VERSION 5.8 ;
BUSBITCHARS "[]" ;
DIVIDERCHAR "/" ;
UNITS
    DATABASE MICRONS 1000 ;
END UNITS

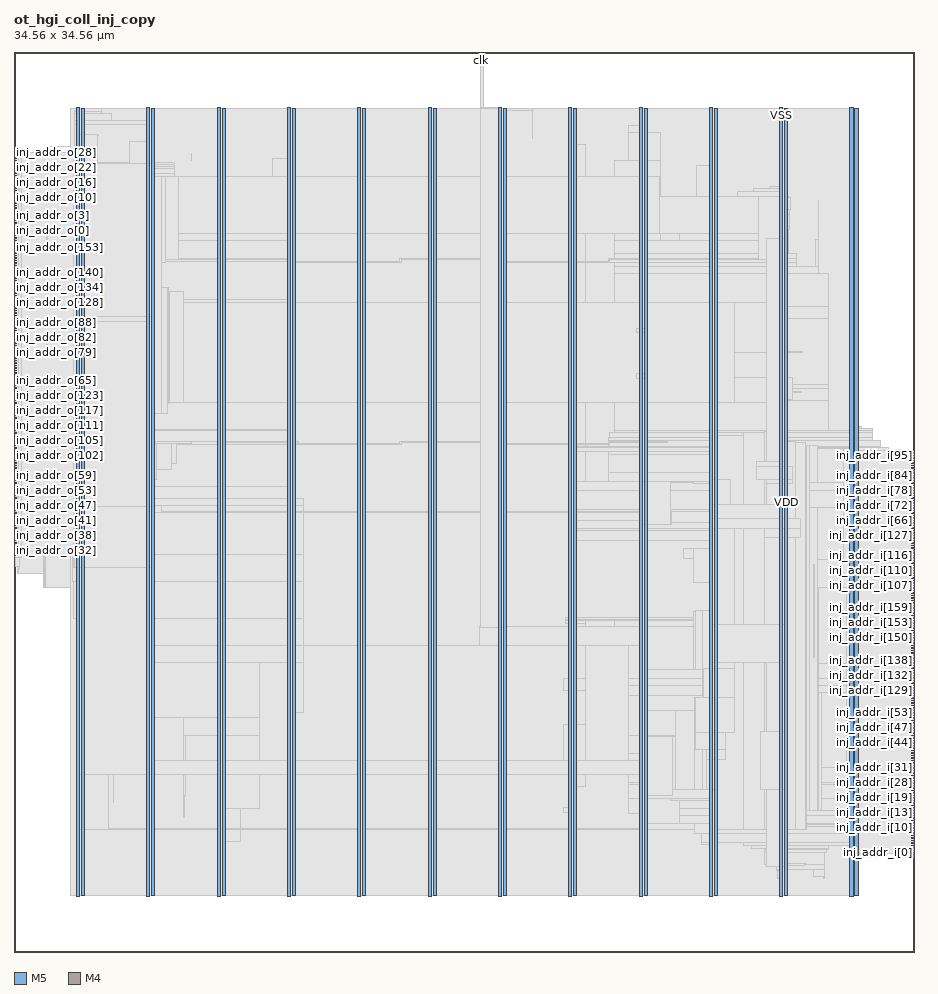
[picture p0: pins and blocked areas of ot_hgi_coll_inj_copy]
MACRO ot_hgi_coll_inj_copy
  FOREIGN ot_hgi_coll_inj_copy 0 0 ;
  CLASS BLOCK ;
  SIZE 34.56 BY 34.56 ;
  PIN clk
    DIRECTION INPUT ;
    USE SIGNAL ;
    PORT
      LAYER M5 ;
        RECT  17.904 34.476 17.928 34.56 ;
    END
  END clk
  PIN inj_addr_i[0]
    DIRECTION INPUT ;
    USE SIGNAL ;
    PORT
      LAYER M4 ;
        RECT  34.476 3.792 34.56 3.816 ;
    END
  END inj_addr_i[0]
  PIN inj_addr_i[100]
    DIRECTION INPUT ;
    USE SIGNAL ;
    PORT
      LAYER M4 ;
        RECT  34.476 13.392 34.56 13.416 ;
    END
  END inj_addr_i[100]
  PIN inj_addr_i[101]
    DIRECTION INPUT ;
    USE SIGNAL ;
    PORT
      LAYER M4 ;
        RECT  34.476 13.488 34.56 13.512 ;
    END
  END inj_addr_i[101]
  PIN inj_addr_i[102]
    DIRECTION INPUT ;
    USE SIGNAL ;
    PORT
      LAYER M4 ;
        RECT  34.476 13.584 34.56 13.608 ;
    END
  END inj_addr_i[102]
  PIN inj_addr_i[103]
    DIRECTION INPUT ;
    USE SIGNAL ;
    PORT
      LAYER M4 ;
        RECT  34.476 13.68 34.56 13.704 ;
    END
  END inj_addr_i[103]
  PIN inj_addr_i[104]
    DIRECTION INPUT ;
    USE SIGNAL ;
    PORT
      LAYER M4 ;
        RECT  34.476 13.776 34.56 13.8 ;
    END
  END inj_addr_i[104]
  PIN inj_addr_i[105]
    DIRECTION INPUT ;
    USE SIGNAL ;
    PORT
      LAYER M4 ;
        RECT  34.476 13.872 34.56 13.896 ;
    END
  END inj_addr_i[105]
  PIN inj_addr_i[106]
    DIRECTION INPUT ;
    USE SIGNAL ;
    PORT
      LAYER M4 ;
        RECT  34.476 13.968 34.56 13.992 ;
    END
  END inj_addr_i[106]
  PIN inj_addr_i[107]
    DIRECTION INPUT ;
    USE SIGNAL ;
    PORT
      LAYER M4 ;
        RECT  34.476 14.064 34.56 14.088 ;
    END
  END inj_addr_i[107]
  PIN inj_addr_i[108]
    DIRECTION INPUT ;
    USE SIGNAL ;
    PORT
      LAYER M4 ;
        RECT  34.476 14.16 34.56 14.184 ;
    END
  END inj_addr_i[108]
  PIN inj_addr_i[109]
    DIRECTION INPUT ;
    USE SIGNAL ;
    PORT
      LAYER M4 ;
        RECT  34.476 14.256 34.56 14.28 ;
    END
  END inj_addr_i[109]
  PIN inj_addr_i[10]
    DIRECTION INPUT ;
    USE SIGNAL ;
    PORT
      LAYER M4 ;
        RECT  34.476 4.752 34.56 4.776 ;
    END
  END inj_addr_i[10]
  PIN inj_addr_i[110]
    DIRECTION INPUT ;
    USE SIGNAL ;
    PORT
      LAYER M4 ;
        RECT  34.476 14.352 34.56 14.376 ;
    END
  END inj_addr_i[110]
  PIN inj_addr_i[111]
    DIRECTION INPUT ;
    USE SIGNAL ;
    PORT
      LAYER M4 ;
        RECT  34.476 14.448 34.56 14.472 ;
    END
  END inj_addr_i[111]
  PIN inj_addr_i[112]
    DIRECTION INPUT ;
    USE SIGNAL ;
    PORT
      LAYER M4 ;
        RECT  34.476 14.544 34.56 14.568 ;
    END
  END inj_addr_i[112]
  PIN inj_addr_i[113]
    DIRECTION INPUT ;
    USE SIGNAL ;
    PORT
      LAYER M4 ;
        RECT  34.476 14.64 34.56 14.664 ;
    END
  END inj_addr_i[113]
  PIN inj_addr_i[114]
    DIRECTION INPUT ;
    USE SIGNAL ;
    PORT
      LAYER M4 ;
        RECT  34.476 14.736 34.56 14.76 ;
    END
  END inj_addr_i[114]
  PIN inj_addr_i[115]
    DIRECTION INPUT ;
    USE SIGNAL ;
    PORT
      LAYER M4 ;
        RECT  34.476 14.832 34.56 14.856 ;
    END
  END inj_addr_i[115]
  PIN inj_addr_i[116]
    DIRECTION INPUT ;
    USE SIGNAL ;
    PORT
      LAYER M4 ;
        RECT  34.476 14.928 34.56 14.952 ;
    END
  END inj_addr_i[116]
  PIN inj_addr_i[117]
    DIRECTION INPUT ;
    USE SIGNAL ;
    PORT
      LAYER M4 ;
        RECT  34.476 15.024 34.56 15.048 ;
    END
  END inj_addr_i[117]
  PIN inj_addr_i[118]
    DIRECTION INPUT ;
    USE SIGNAL ;
    PORT
      LAYER M4 ;
        RECT  34.476 15.12 34.56 15.144 ;
    END
  END inj_addr_i[118]
  PIN inj_addr_i[119]
    DIRECTION INPUT ;
    USE SIGNAL ;
    PORT
      LAYER M4 ;
        RECT  34.476 15.216 34.56 15.24 ;
    END
  END inj_addr_i[119]
  PIN inj_addr_i[11]
    DIRECTION INPUT ;
    USE SIGNAL ;
    PORT
      LAYER M4 ;
        RECT  34.476 4.848 34.56 4.872 ;
    END
  END inj_addr_i[11]
  PIN inj_addr_i[120]
    DIRECTION INPUT ;
    USE SIGNAL ;
    PORT
      LAYER M4 ;
        RECT  34.476 15.312 34.56 15.336 ;
    END
  END inj_addr_i[120]
  PIN inj_addr_i[121]
    DIRECTION INPUT ;
    USE SIGNAL ;
    PORT
      LAYER M4 ;
        RECT  34.476 15.408 34.56 15.432 ;
    END
  END inj_addr_i[121]
  PIN inj_addr_i[122]
    DIRECTION INPUT ;
    USE SIGNAL ;
    PORT
      LAYER M4 ;
        RECT  34.476 15.504 34.56 15.528 ;
    END
  END inj_addr_i[122]
  PIN inj_addr_i[123]
    DIRECTION INPUT ;
    USE SIGNAL ;
    PORT
      LAYER M4 ;
        RECT  34.476 15.6 34.56 15.624 ;
    END
  END inj_addr_i[123]
  PIN inj_addr_i[124]
    DIRECTION INPUT ;
    USE SIGNAL ;
    PORT
      LAYER M4 ;
        RECT  34.476 15.696 34.56 15.72 ;
    END
  END inj_addr_i[124]
  PIN inj_addr_i[125]
    DIRECTION INPUT ;
    USE SIGNAL ;
    PORT
      LAYER M4 ;
        RECT  34.476 15.792 34.56 15.816 ;
    END
  END inj_addr_i[125]
  PIN inj_addr_i[126]
    DIRECTION INPUT ;
    USE SIGNAL ;
    PORT
      LAYER M4 ;
        RECT  34.476 15.888 34.56 15.912 ;
    END
  END inj_addr_i[126]
  PIN inj_addr_i[127]
    DIRECTION INPUT ;
    USE SIGNAL ;
    PORT
      LAYER M4 ;
        RECT  34.476 15.984 34.56 16.008 ;
    END
  END inj_addr_i[127]
  PIN inj_addr_i[128]
    DIRECTION INPUT ;
    USE SIGNAL ;
    PORT
      LAYER M4 ;
        RECT  34.476 9.936 34.56 9.96 ;
    END
  END inj_addr_i[128]
  PIN inj_addr_i[129]
    DIRECTION INPUT ;
    USE SIGNAL ;
    PORT
      LAYER M4 ;
        RECT  34.476 10.032 34.56 10.056 ;
    END
  END inj_addr_i[129]
  PIN inj_addr_i[12]
    DIRECTION INPUT ;
    USE SIGNAL ;
    PORT
      LAYER M4 ;
        RECT  34.476 4.944 34.56 4.968 ;
    END
  END inj_addr_i[12]
  PIN inj_addr_i[130]
    DIRECTION INPUT ;
    USE SIGNAL ;
    PORT
      LAYER M4 ;
        RECT  34.476 10.128 34.56 10.152 ;
    END
  END inj_addr_i[130]
  PIN inj_addr_i[131]
    DIRECTION INPUT ;
    USE SIGNAL ;
    PORT
      LAYER M4 ;
        RECT  34.476 10.224 34.56 10.248 ;
    END
  END inj_addr_i[131]
  PIN inj_addr_i[132]
    DIRECTION INPUT ;
    USE SIGNAL ;
    PORT
      LAYER M4 ;
        RECT  34.476 10.32 34.56 10.344 ;
    END
  END inj_addr_i[132]
  PIN inj_addr_i[133]
    DIRECTION INPUT ;
    USE SIGNAL ;
    PORT
      LAYER M4 ;
        RECT  34.476 10.416 34.56 10.44 ;
    END
  END inj_addr_i[133]
  PIN inj_addr_i[134]
    DIRECTION INPUT ;
    USE SIGNAL ;
    PORT
      LAYER M4 ;
        RECT  34.476 10.512 34.56 10.536 ;
    END
  END inj_addr_i[134]
  PIN inj_addr_i[135]
    DIRECTION INPUT ;
    USE SIGNAL ;
    PORT
      LAYER M4 ;
        RECT  34.476 10.608 34.56 10.632 ;
    END
  END inj_addr_i[135]
  PIN inj_addr_i[136]
    DIRECTION INPUT ;
    USE SIGNAL ;
    PORT
      LAYER M4 ;
        RECT  34.476 10.704 34.56 10.728 ;
    END
  END inj_addr_i[136]
  PIN inj_addr_i[137]
    DIRECTION INPUT ;
    USE SIGNAL ;
    PORT
      LAYER M4 ;
        RECT  34.476 10.8 34.56 10.824 ;
    END
  END inj_addr_i[137]
  PIN inj_addr_i[138]
    DIRECTION INPUT ;
    USE SIGNAL ;
    PORT
      LAYER M4 ;
        RECT  34.476 10.896 34.56 10.92 ;
    END
  END inj_addr_i[138]
  PIN inj_addr_i[139]
    DIRECTION INPUT ;
    USE SIGNAL ;
    PORT
      LAYER M4 ;
        RECT  34.476 10.992 34.56 11.016 ;
    END
  END inj_addr_i[139]
  PIN inj_addr_i[13]
    DIRECTION INPUT ;
    USE SIGNAL ;
    PORT
      LAYER M4 ;
        RECT  34.476 5.04 34.56 5.064 ;
    END
  END inj_addr_i[13]
  PIN inj_addr_i[140]
    DIRECTION INPUT ;
    USE SIGNAL ;
    PORT
      LAYER M4 ;
        RECT  34.476 11.088 34.56 11.112 ;
    END
  END inj_addr_i[140]
  PIN inj_addr_i[141]
    DIRECTION INPUT ;
    USE SIGNAL ;
    PORT
      LAYER M4 ;
        RECT  34.476 11.184 34.56 11.208 ;
    END
  END inj_addr_i[141]
  PIN inj_addr_i[142]
    DIRECTION INPUT ;
    USE SIGNAL ;
    PORT
      LAYER M4 ;
        RECT  34.476 11.28 34.56 11.304 ;
    END
  END inj_addr_i[142]
  PIN inj_addr_i[143]
    DIRECTION INPUT ;
    USE SIGNAL ;
    PORT
      LAYER M4 ;
        RECT  34.476 11.376 34.56 11.4 ;
    END
  END inj_addr_i[143]
  PIN inj_addr_i[144]
    DIRECTION INPUT ;
    USE SIGNAL ;
    PORT
      LAYER M4 ;
        RECT  34.476 11.472 34.56 11.496 ;
    END
  END inj_addr_i[144]
  PIN inj_addr_i[145]
    DIRECTION INPUT ;
    USE SIGNAL ;
    PORT
      LAYER M4 ;
        RECT  34.476 11.568 34.56 11.592 ;
    END
  END inj_addr_i[145]
  PIN inj_addr_i[146]
    DIRECTION INPUT ;
    USE SIGNAL ;
    PORT
      LAYER M4 ;
        RECT  34.476 11.664 34.56 11.688 ;
    END
  END inj_addr_i[146]
  PIN inj_addr_i[147]
    DIRECTION INPUT ;
    USE SIGNAL ;
    PORT
      LAYER M4 ;
        RECT  34.476 11.76 34.56 11.784 ;
    END
  END inj_addr_i[147]
  PIN inj_addr_i[148]
    DIRECTION INPUT ;
    USE SIGNAL ;
    PORT
      LAYER M4 ;
        RECT  34.476 11.856 34.56 11.88 ;
    END
  END inj_addr_i[148]
  PIN inj_addr_i[149]
    DIRECTION INPUT ;
    USE SIGNAL ;
    PORT
      LAYER M4 ;
        RECT  34.476 11.952 34.56 11.976 ;
    END
  END inj_addr_i[149]
  PIN inj_addr_i[14]
    DIRECTION INPUT ;
    USE SIGNAL ;
    PORT
      LAYER M4 ;
        RECT  34.476 5.136 34.56 5.16 ;
    END
  END inj_addr_i[14]
  PIN inj_addr_i[150]
    DIRECTION INPUT ;
    USE SIGNAL ;
    PORT
      LAYER M4 ;
        RECT  34.476 12.048 34.56 12.072 ;
    END
  END inj_addr_i[150]
  PIN inj_addr_i[151]
    DIRECTION INPUT ;
    USE SIGNAL ;
    PORT
      LAYER M4 ;
        RECT  34.476 12.144 34.56 12.168 ;
    END
  END inj_addr_i[151]
  PIN inj_addr_i[152]
    DIRECTION INPUT ;
    USE SIGNAL ;
    PORT
      LAYER M4 ;
        RECT  34.476 12.24 34.56 12.264 ;
    END
  END inj_addr_i[152]
  PIN inj_addr_i[153]
    DIRECTION INPUT ;
    USE SIGNAL ;
    PORT
      LAYER M4 ;
        RECT  34.476 12.336 34.56 12.36 ;
    END
  END inj_addr_i[153]
  PIN inj_addr_i[154]
    DIRECTION INPUT ;
    USE SIGNAL ;
    PORT
      LAYER M4 ;
        RECT  34.476 12.432 34.56 12.456 ;
    END
  END inj_addr_i[154]
  PIN inj_addr_i[155]
    DIRECTION INPUT ;
    USE SIGNAL ;
    PORT
      LAYER M4 ;
        RECT  34.476 12.528 34.56 12.552 ;
    END
  END inj_addr_i[155]
  PIN inj_addr_i[156]
    DIRECTION INPUT ;
    USE SIGNAL ;
    PORT
      LAYER M4 ;
        RECT  34.476 12.624 34.56 12.648 ;
    END
  END inj_addr_i[156]
  PIN inj_addr_i[157]
    DIRECTION INPUT ;
    USE SIGNAL ;
    PORT
      LAYER M4 ;
        RECT  34.476 12.72 34.56 12.744 ;
    END
  END inj_addr_i[157]
  PIN inj_addr_i[158]
    DIRECTION INPUT ;
    USE SIGNAL ;
    PORT
      LAYER M4 ;
        RECT  34.476 12.816 34.56 12.84 ;
    END
  END inj_addr_i[158]
  PIN inj_addr_i[159]
    DIRECTION INPUT ;
    USE SIGNAL ;
    PORT
      LAYER M4 ;
        RECT  34.476 12.912 34.56 12.936 ;
    END
  END inj_addr_i[159]
  PIN inj_addr_i[15]
    DIRECTION INPUT ;
    USE SIGNAL ;
    PORT
      LAYER M4 ;
        RECT  34.476 5.232 34.56 5.256 ;
    END
  END inj_addr_i[15]
  PIN inj_addr_i[16]
    DIRECTION INPUT ;
    USE SIGNAL ;
    PORT
      LAYER M4 ;
        RECT  34.476 5.328 34.56 5.352 ;
    END
  END inj_addr_i[16]
  PIN inj_addr_i[17]
    DIRECTION INPUT ;
    USE SIGNAL ;
    PORT
      LAYER M4 ;
        RECT  34.476 5.424 34.56 5.448 ;
    END
  END inj_addr_i[17]
  PIN inj_addr_i[18]
    DIRECTION INPUT ;
    USE SIGNAL ;
    PORT
      LAYER M4 ;
        RECT  34.476 5.52 34.56 5.544 ;
    END
  END inj_addr_i[18]
  PIN inj_addr_i[19]
    DIRECTION INPUT ;
    USE SIGNAL ;
    PORT
      LAYER M4 ;
        RECT  34.476 5.616 34.56 5.64 ;
    END
  END inj_addr_i[19]
  PIN inj_addr_i[1]
    DIRECTION INPUT ;
    USE SIGNAL ;
    PORT
      LAYER M4 ;
        RECT  34.476 3.888 34.56 3.912 ;
    END
  END inj_addr_i[1]
  PIN inj_addr_i[20]
    DIRECTION INPUT ;
    USE SIGNAL ;
    PORT
      LAYER M4 ;
        RECT  34.476 5.712 34.56 5.736 ;
    END
  END inj_addr_i[20]
  PIN inj_addr_i[21]
    DIRECTION INPUT ;
    USE SIGNAL ;
    PORT
      LAYER M4 ;
        RECT  34.476 5.808 34.56 5.832 ;
    END
  END inj_addr_i[21]
  PIN inj_addr_i[22]
    DIRECTION INPUT ;
    USE SIGNAL ;
    PORT
      LAYER M4 ;
        RECT  34.476 5.904 34.56 5.928 ;
    END
  END inj_addr_i[22]
  PIN inj_addr_i[23]
    DIRECTION INPUT ;
    USE SIGNAL ;
    PORT
      LAYER M4 ;
        RECT  34.476 6 34.56 6.024 ;
    END
  END inj_addr_i[23]
  PIN inj_addr_i[24]
    DIRECTION INPUT ;
    USE SIGNAL ;
    PORT
      LAYER M4 ;
        RECT  34.476 6.096 34.56 6.12 ;
    END
  END inj_addr_i[24]
  PIN inj_addr_i[25]
    DIRECTION INPUT ;
    USE SIGNAL ;
    PORT
      LAYER M4 ;
        RECT  34.476 6.192 34.56 6.216 ;
    END
  END inj_addr_i[25]
  PIN inj_addr_i[26]
    DIRECTION INPUT ;
    USE SIGNAL ;
    PORT
      LAYER M4 ;
        RECT  34.476 6.288 34.56 6.312 ;
    END
  END inj_addr_i[26]
  PIN inj_addr_i[27]
    DIRECTION INPUT ;
    USE SIGNAL ;
    PORT
      LAYER M4 ;
        RECT  34.476 6.384 34.56 6.408 ;
    END
  END inj_addr_i[27]
  PIN inj_addr_i[28]
    DIRECTION INPUT ;
    USE SIGNAL ;
    PORT
      LAYER M4 ;
        RECT  34.476 6.48 34.56 6.504 ;
    END
  END inj_addr_i[28]
  PIN inj_addr_i[29]
    DIRECTION INPUT ;
    USE SIGNAL ;
    PORT
      LAYER M4 ;
        RECT  34.476 6.576 34.56 6.6 ;
    END
  END inj_addr_i[29]
  PIN inj_addr_i[2]
    DIRECTION INPUT ;
    USE SIGNAL ;
    PORT
      LAYER M4 ;
        RECT  34.476 3.984 34.56 4.008 ;
    END
  END inj_addr_i[2]
  PIN inj_addr_i[30]
    DIRECTION INPUT ;
    USE SIGNAL ;
    PORT
      LAYER M4 ;
        RECT  34.476 6.672 34.56 6.696 ;
    END
  END inj_addr_i[30]
  PIN inj_addr_i[31]
    DIRECTION INPUT ;
    USE SIGNAL ;
    PORT
      LAYER M4 ;
        RECT  34.476 6.768 34.56 6.792 ;
    END
  END inj_addr_i[31]
  PIN inj_addr_i[32]
    DIRECTION INPUT ;
    USE SIGNAL ;
    PORT
      LAYER M4 ;
        RECT  34.476 6.864 34.56 6.888 ;
    END
  END inj_addr_i[32]
  PIN inj_addr_i[33]
    DIRECTION INPUT ;
    USE SIGNAL ;
    PORT
      LAYER M4 ;
        RECT  34.476 6.96 34.56 6.984 ;
    END
  END inj_addr_i[33]
  PIN inj_addr_i[34]
    DIRECTION INPUT ;
    USE SIGNAL ;
    PORT
      LAYER M4 ;
        RECT  34.476 7.056 34.56 7.08 ;
    END
  END inj_addr_i[34]
  PIN inj_addr_i[35]
    DIRECTION INPUT ;
    USE SIGNAL ;
    PORT
      LAYER M4 ;
        RECT  34.476 7.152 34.56 7.176 ;
    END
  END inj_addr_i[35]
  PIN inj_addr_i[36]
    DIRECTION INPUT ;
    USE SIGNAL ;
    PORT
      LAYER M4 ;
        RECT  34.476 7.248 34.56 7.272 ;
    END
  END inj_addr_i[36]
  PIN inj_addr_i[37]
    DIRECTION INPUT ;
    USE SIGNAL ;
    PORT
      LAYER M4 ;
        RECT  34.476 7.344 34.56 7.368 ;
    END
  END inj_addr_i[37]
  PIN inj_addr_i[38]
    DIRECTION INPUT ;
    USE SIGNAL ;
    PORT
      LAYER M4 ;
        RECT  34.476 7.44 34.56 7.464 ;
    END
  END inj_addr_i[38]
  PIN inj_addr_i[39]
    DIRECTION INPUT ;
    USE SIGNAL ;
    PORT
      LAYER M4 ;
        RECT  34.476 7.536 34.56 7.56 ;
    END
  END inj_addr_i[39]
  PIN inj_addr_i[3]
    DIRECTION INPUT ;
    USE SIGNAL ;
    PORT
      LAYER M4 ;
        RECT  34.476 4.08 34.56 4.104 ;
    END
  END inj_addr_i[3]
  PIN inj_addr_i[40]
    DIRECTION INPUT ;
    USE SIGNAL ;
    PORT
      LAYER M4 ;
        RECT  34.476 7.632 34.56 7.656 ;
    END
  END inj_addr_i[40]
  PIN inj_addr_i[41]
    DIRECTION INPUT ;
    USE SIGNAL ;
    PORT
      LAYER M4 ;
        RECT  34.476 7.728 34.56 7.752 ;
    END
  END inj_addr_i[41]
  PIN inj_addr_i[42]
    DIRECTION INPUT ;
    USE SIGNAL ;
    PORT
      LAYER M4 ;
        RECT  34.476 7.824 34.56 7.848 ;
    END
  END inj_addr_i[42]
  PIN inj_addr_i[43]
    DIRECTION INPUT ;
    USE SIGNAL ;
    PORT
      LAYER M4 ;
        RECT  34.476 7.92 34.56 7.944 ;
    END
  END inj_addr_i[43]
  PIN inj_addr_i[44]
    DIRECTION INPUT ;
    USE SIGNAL ;
    PORT
      LAYER M4 ;
        RECT  34.476 8.016 34.56 8.04 ;
    END
  END inj_addr_i[44]
  PIN inj_addr_i[45]
    DIRECTION INPUT ;
    USE SIGNAL ;
    PORT
      LAYER M4 ;
        RECT  34.476 8.112 34.56 8.136 ;
    END
  END inj_addr_i[45]
  PIN inj_addr_i[46]
    DIRECTION INPUT ;
    USE SIGNAL ;
    PORT
      LAYER M4 ;
        RECT  34.476 8.208 34.56 8.232 ;
    END
  END inj_addr_i[46]
  PIN inj_addr_i[47]
    DIRECTION INPUT ;
    USE SIGNAL ;
    PORT
      LAYER M4 ;
        RECT  34.476 8.304 34.56 8.328 ;
    END
  END inj_addr_i[47]
  PIN inj_addr_i[48]
    DIRECTION INPUT ;
    USE SIGNAL ;
    PORT
      LAYER M4 ;
        RECT  34.476 8.4 34.56 8.424 ;
    END
  END inj_addr_i[48]
  PIN inj_addr_i[49]
    DIRECTION INPUT ;
    USE SIGNAL ;
    PORT
      LAYER M4 ;
        RECT  34.476 8.496 34.56 8.52 ;
    END
  END inj_addr_i[49]
  PIN inj_addr_i[4]
    DIRECTION INPUT ;
    USE SIGNAL ;
    PORT
      LAYER M4 ;
        RECT  34.476 4.176 34.56 4.2 ;
    END
  END inj_addr_i[4]
  PIN inj_addr_i[50]
    DIRECTION INPUT ;
    USE SIGNAL ;
    PORT
      LAYER M4 ;
        RECT  34.476 8.592 34.56 8.616 ;
    END
  END inj_addr_i[50]
  PIN inj_addr_i[51]
    DIRECTION INPUT ;
    USE SIGNAL ;
    PORT
      LAYER M4 ;
        RECT  34.476 8.688 34.56 8.712 ;
    END
  END inj_addr_i[51]
  PIN inj_addr_i[52]
    DIRECTION INPUT ;
    USE SIGNAL ;
    PORT
      LAYER M4 ;
        RECT  34.476 8.784 34.56 8.808 ;
    END
  END inj_addr_i[52]
  PIN inj_addr_i[53]
    DIRECTION INPUT ;
    USE SIGNAL ;
    PORT
      LAYER M4 ;
        RECT  34.476 8.88 34.56 8.904 ;
    END
  END inj_addr_i[53]
  PIN inj_addr_i[54]
    DIRECTION INPUT ;
    USE SIGNAL ;
    PORT
      LAYER M4 ;
        RECT  34.476 8.976 34.56 9 ;
    END
  END inj_addr_i[54]
  PIN inj_addr_i[55]
    DIRECTION INPUT ;
    USE SIGNAL ;
    PORT
      LAYER M4 ;
        RECT  34.476 9.072 34.56 9.096 ;
    END
  END inj_addr_i[55]
  PIN inj_addr_i[56]
    DIRECTION INPUT ;
    USE SIGNAL ;
    PORT
      LAYER M4 ;
        RECT  34.476 9.168 34.56 9.192 ;
    END
  END inj_addr_i[56]
  PIN inj_addr_i[57]
    DIRECTION INPUT ;
    USE SIGNAL ;
    PORT
      LAYER M4 ;
        RECT  34.476 9.264 34.56 9.288 ;
    END
  END inj_addr_i[57]
  PIN inj_addr_i[58]
    DIRECTION INPUT ;
    USE SIGNAL ;
    PORT
      LAYER M4 ;
        RECT  34.476 9.36 34.56 9.384 ;
    END
  END inj_addr_i[58]
  PIN inj_addr_i[59]
    DIRECTION INPUT ;
    USE SIGNAL ;
    PORT
      LAYER M4 ;
        RECT  34.476 9.456 34.56 9.48 ;
    END
  END inj_addr_i[59]
  PIN inj_addr_i[5]
    DIRECTION INPUT ;
    USE SIGNAL ;
    PORT
      LAYER M4 ;
        RECT  34.476 4.272 34.56 4.296 ;
    END
  END inj_addr_i[5]
  PIN inj_addr_i[60]
    DIRECTION INPUT ;
    USE SIGNAL ;
    PORT
      LAYER M4 ;
        RECT  34.476 9.552 34.56 9.576 ;
    END
  END inj_addr_i[60]
  PIN inj_addr_i[61]
    DIRECTION INPUT ;
    USE SIGNAL ;
    PORT
      LAYER M4 ;
        RECT  34.476 9.648 34.56 9.672 ;
    END
  END inj_addr_i[61]
  PIN inj_addr_i[62]
    DIRECTION INPUT ;
    USE SIGNAL ;
    PORT
      LAYER M4 ;
        RECT  34.476 9.744 34.56 9.768 ;
    END
  END inj_addr_i[62]
  PIN inj_addr_i[63]
    DIRECTION INPUT ;
    USE SIGNAL ;
    PORT
      LAYER M4 ;
        RECT  34.476 9.84 34.56 9.864 ;
    END
  END inj_addr_i[63]
  PIN inj_addr_i[64]
    DIRECTION INPUT ;
    USE SIGNAL ;
    PORT
      LAYER M4 ;
        RECT  34.476 16.08 34.56 16.104 ;
    END
  END inj_addr_i[64]
  PIN inj_addr_i[65]
    DIRECTION INPUT ;
    USE SIGNAL ;
    PORT
      LAYER M4 ;
        RECT  34.476 16.176 34.56 16.2 ;
    END
  END inj_addr_i[65]
  PIN inj_addr_i[66]
    DIRECTION INPUT ;
    USE SIGNAL ;
    PORT
      LAYER M4 ;
        RECT  34.476 16.272 34.56 16.296 ;
    END
  END inj_addr_i[66]
  PIN inj_addr_i[67]
    DIRECTION INPUT ;
    USE SIGNAL ;
    PORT
      LAYER M4 ;
        RECT  34.476 16.368 34.56 16.392 ;
    END
  END inj_addr_i[67]
  PIN inj_addr_i[68]
    DIRECTION INPUT ;
    USE SIGNAL ;
    PORT
      LAYER M4 ;
        RECT  34.476 16.464 34.56 16.488 ;
    END
  END inj_addr_i[68]
  PIN inj_addr_i[69]
    DIRECTION INPUT ;
    USE SIGNAL ;
    PORT
      LAYER M4 ;
        RECT  34.476 16.56 34.56 16.584 ;
    END
  END inj_addr_i[69]
  PIN inj_addr_i[6]
    DIRECTION INPUT ;
    USE SIGNAL ;
    PORT
      LAYER M4 ;
        RECT  34.476 4.368 34.56 4.392 ;
    END
  END inj_addr_i[6]
  PIN inj_addr_i[70]
    DIRECTION INPUT ;
    USE SIGNAL ;
    PORT
      LAYER M4 ;
        RECT  34.476 16.656 34.56 16.68 ;
    END
  END inj_addr_i[70]
  PIN inj_addr_i[71]
    DIRECTION INPUT ;
    USE SIGNAL ;
    PORT
      LAYER M4 ;
        RECT  34.476 16.752 34.56 16.776 ;
    END
  END inj_addr_i[71]
  PIN inj_addr_i[72]
    DIRECTION INPUT ;
    USE SIGNAL ;
    PORT
      LAYER M4 ;
        RECT  34.476 16.848 34.56 16.872 ;
    END
  END inj_addr_i[72]
  PIN inj_addr_i[73]
    DIRECTION INPUT ;
    USE SIGNAL ;
    PORT
      LAYER M4 ;
        RECT  34.476 16.944 34.56 16.968 ;
    END
  END inj_addr_i[73]
  PIN inj_addr_i[74]
    DIRECTION INPUT ;
    USE SIGNAL ;
    PORT
      LAYER M4 ;
        RECT  34.476 17.04 34.56 17.064 ;
    END
  END inj_addr_i[74]
  PIN inj_addr_i[75]
    DIRECTION INPUT ;
    USE SIGNAL ;
    PORT
      LAYER M4 ;
        RECT  34.476 17.136 34.56 17.16 ;
    END
  END inj_addr_i[75]
  PIN inj_addr_i[76]
    DIRECTION INPUT ;
    USE SIGNAL ;
    PORT
      LAYER M4 ;
        RECT  34.476 17.232 34.56 17.256 ;
    END
  END inj_addr_i[76]
  PIN inj_addr_i[77]
    DIRECTION INPUT ;
    USE SIGNAL ;
    PORT
      LAYER M4 ;
        RECT  34.476 17.328 34.56 17.352 ;
    END
  END inj_addr_i[77]
  PIN inj_addr_i[78]
    DIRECTION INPUT ;
    USE SIGNAL ;
    PORT
      LAYER M4 ;
        RECT  34.476 17.424 34.56 17.448 ;
    END
  END inj_addr_i[78]
  PIN inj_addr_i[79]
    DIRECTION INPUT ;
    USE SIGNAL ;
    PORT
      LAYER M4 ;
        RECT  34.476 17.52 34.56 17.544 ;
    END
  END inj_addr_i[79]
  PIN inj_addr_i[7]
    DIRECTION INPUT ;
    USE SIGNAL ;
    PORT
      LAYER M4 ;
        RECT  34.476 4.464 34.56 4.488 ;
    END
  END inj_addr_i[7]
  PIN inj_addr_i[80]
    DIRECTION INPUT ;
    USE SIGNAL ;
    PORT
      LAYER M4 ;
        RECT  34.476 17.616 34.56 17.64 ;
    END
  END inj_addr_i[80]
  PIN inj_addr_i[81]
    DIRECTION INPUT ;
    USE SIGNAL ;
    PORT
      LAYER M4 ;
        RECT  34.476 17.712 34.56 17.736 ;
    END
  END inj_addr_i[81]
  PIN inj_addr_i[82]
    DIRECTION INPUT ;
    USE SIGNAL ;
    PORT
      LAYER M4 ;
        RECT  34.476 17.808 34.56 17.832 ;
    END
  END inj_addr_i[82]
  PIN inj_addr_i[83]
    DIRECTION INPUT ;
    USE SIGNAL ;
    PORT
      LAYER M4 ;
        RECT  34.476 17.904 34.56 17.928 ;
    END
  END inj_addr_i[83]
  PIN inj_addr_i[84]
    DIRECTION INPUT ;
    USE SIGNAL ;
    PORT
      LAYER M4 ;
        RECT  34.476 18 34.56 18.024 ;
    END
  END inj_addr_i[84]
  PIN inj_addr_i[85]
    DIRECTION INPUT ;
    USE SIGNAL ;
    PORT
      LAYER M4 ;
        RECT  34.476 18.096 34.56 18.12 ;
    END
  END inj_addr_i[85]
  PIN inj_addr_i[86]
    DIRECTION INPUT ;
    USE SIGNAL ;
    PORT
      LAYER M4 ;
        RECT  34.476 18.192 34.56 18.216 ;
    END
  END inj_addr_i[86]
  PIN inj_addr_i[87]
    DIRECTION INPUT ;
    USE SIGNAL ;
    PORT
      LAYER M4 ;
        RECT  34.476 18.288 34.56 18.312 ;
    END
  END inj_addr_i[87]
  PIN inj_addr_i[88]
    DIRECTION INPUT ;
    USE SIGNAL ;
    PORT
      LAYER M4 ;
        RECT  34.476 18.384 34.56 18.408 ;
    END
  END inj_addr_i[88]
  PIN inj_addr_i[89]
    DIRECTION INPUT ;
    USE SIGNAL ;
    PORT
      LAYER M4 ;
        RECT  34.476 18.48 34.56 18.504 ;
    END
  END inj_addr_i[89]
  PIN inj_addr_i[8]
    DIRECTION INPUT ;
    USE SIGNAL ;
    PORT
      LAYER M4 ;
        RECT  34.476 4.56 34.56 4.584 ;
    END
  END inj_addr_i[8]
  PIN inj_addr_i[90]
    DIRECTION INPUT ;
    USE SIGNAL ;
    PORT
      LAYER M4 ;
        RECT  34.476 18.576 34.56 18.6 ;
    END
  END inj_addr_i[90]
  PIN inj_addr_i[91]
    DIRECTION INPUT ;
    USE SIGNAL ;
    PORT
      LAYER M4 ;
        RECT  34.476 18.672 34.56 18.696 ;
    END
  END inj_addr_i[91]
  PIN inj_addr_i[92]
    DIRECTION INPUT ;
    USE SIGNAL ;
    PORT
      LAYER M4 ;
        RECT  34.476 18.768 34.56 18.792 ;
    END
  END inj_addr_i[92]
  PIN inj_addr_i[93]
    DIRECTION INPUT ;
    USE SIGNAL ;
    PORT
      LAYER M4 ;
        RECT  34.476 18.864 34.56 18.888 ;
    END
  END inj_addr_i[93]
  PIN inj_addr_i[94]
    DIRECTION INPUT ;
    USE SIGNAL ;
    PORT
      LAYER M4 ;
        RECT  34.476 18.96 34.56 18.984 ;
    END
  END inj_addr_i[94]
  PIN inj_addr_i[95]
    DIRECTION INPUT ;
    USE SIGNAL ;
    PORT
      LAYER M4 ;
        RECT  34.476 19.056 34.56 19.08 ;
    END
  END inj_addr_i[95]
  PIN inj_addr_i[96]
    DIRECTION INPUT ;
    USE SIGNAL ;
    PORT
      LAYER M4 ;
        RECT  34.476 13.008 34.56 13.032 ;
    END
  END inj_addr_i[96]
  PIN inj_addr_i[97]
    DIRECTION INPUT ;
    USE SIGNAL ;
    PORT
      LAYER M4 ;
        RECT  34.476 13.104 34.56 13.128 ;
    END
  END inj_addr_i[97]
  PIN inj_addr_i[98]
    DIRECTION INPUT ;
    USE SIGNAL ;
    PORT
      LAYER M4 ;
        RECT  34.476 13.2 34.56 13.224 ;
    END
  END inj_addr_i[98]
  PIN inj_addr_i[99]
    DIRECTION INPUT ;
    USE SIGNAL ;
    PORT
      LAYER M4 ;
        RECT  34.476 13.296 34.56 13.32 ;
    END
  END inj_addr_i[99]
  PIN inj_addr_i[9]
    DIRECTION INPUT ;
    USE SIGNAL ;
    PORT
      LAYER M4 ;
        RECT  34.476 4.656 34.56 4.68 ;
    END
  END inj_addr_i[9]
  PIN inj_addr_o[0]
    DIRECTION OUTPUT ;
    USE SIGNAL ;
    PORT
      LAYER M4 ;
        RECT  0 27.696 0.084 27.72 ;
    END
  END inj_addr_o[0]
  PIN inj_addr_o[100]
    DIRECTION OUTPUT ;
    USE SIGNAL ;
    PORT
      LAYER M4 ;
        RECT  0 18.864 0.084 18.888 ;
    END
  END inj_addr_o[100]
  PIN inj_addr_o[101]
    DIRECTION OUTPUT ;
    USE SIGNAL ;
    PORT
      LAYER M4 ;
        RECT  0 18.96 0.084 18.984 ;
    END
  END inj_addr_o[101]
  PIN inj_addr_o[102]
    DIRECTION OUTPUT ;
    USE SIGNAL ;
    PORT
      LAYER M4 ;
        RECT  0 19.056 0.084 19.08 ;
    END
  END inj_addr_o[102]
  PIN inj_addr_o[103]
    DIRECTION OUTPUT ;
    USE SIGNAL ;
    PORT
      LAYER M4 ;
        RECT  0 19.152 0.084 19.176 ;
    END
  END inj_addr_o[103]
  PIN inj_addr_o[104]
    DIRECTION OUTPUT ;
    USE SIGNAL ;
    PORT
      LAYER M4 ;
        RECT  0 19.248 0.084 19.272 ;
    END
  END inj_addr_o[104]
  PIN inj_addr_o[105]
    DIRECTION OUTPUT ;
    USE SIGNAL ;
    PORT
      LAYER M4 ;
        RECT  0 19.344 0.084 19.368 ;
    END
  END inj_addr_o[105]
  PIN inj_addr_o[106]
    DIRECTION OUTPUT ;
    USE SIGNAL ;
    PORT
      LAYER M4 ;
        RECT  0 19.44 0.084 19.464 ;
    END
  END inj_addr_o[106]
  PIN inj_addr_o[107]
    DIRECTION OUTPUT ;
    USE SIGNAL ;
    PORT
      LAYER M4 ;
        RECT  0 19.536 0.084 19.56 ;
    END
  END inj_addr_o[107]
  PIN inj_addr_o[108]
    DIRECTION OUTPUT ;
    USE SIGNAL ;
    PORT
      LAYER M4 ;
        RECT  0 19.632 0.084 19.656 ;
    END
  END inj_addr_o[108]
  PIN inj_addr_o[109]
    DIRECTION OUTPUT ;
    USE SIGNAL ;
    PORT
      LAYER M4 ;
        RECT  0 19.728 0.084 19.752 ;
    END
  END inj_addr_o[109]
  PIN inj_addr_o[10]
    DIRECTION OUTPUT ;
    USE SIGNAL ;
    PORT
      LAYER M4 ;
        RECT  0 28.656 0.084 28.68 ;
    END
  END inj_addr_o[10]
  PIN inj_addr_o[110]
    DIRECTION OUTPUT ;
    USE SIGNAL ;
    PORT
      LAYER M4 ;
        RECT  0 19.824 0.084 19.848 ;
    END
  END inj_addr_o[110]
  PIN inj_addr_o[111]
    DIRECTION OUTPUT ;
    USE SIGNAL ;
    PORT
      LAYER M4 ;
        RECT  0 19.92 0.084 19.944 ;
    END
  END inj_addr_o[111]
  PIN inj_addr_o[112]
    DIRECTION OUTPUT ;
    USE SIGNAL ;
    PORT
      LAYER M4 ;
        RECT  0 20.016 0.084 20.04 ;
    END
  END inj_addr_o[112]
  PIN inj_addr_o[113]
    DIRECTION OUTPUT ;
    USE SIGNAL ;
    PORT
      LAYER M4 ;
        RECT  0 20.112 0.084 20.136 ;
    END
  END inj_addr_o[113]
  PIN inj_addr_o[114]
    DIRECTION OUTPUT ;
    USE SIGNAL ;
    PORT
      LAYER M4 ;
        RECT  0 20.208 0.084 20.232 ;
    END
  END inj_addr_o[114]
  PIN inj_addr_o[115]
    DIRECTION OUTPUT ;
    USE SIGNAL ;
    PORT
      LAYER M4 ;
        RECT  0 20.304 0.084 20.328 ;
    END
  END inj_addr_o[115]
  PIN inj_addr_o[116]
    DIRECTION OUTPUT ;
    USE SIGNAL ;
    PORT
      LAYER M4 ;
        RECT  0 20.4 0.084 20.424 ;
    END
  END inj_addr_o[116]
  PIN inj_addr_o[117]
    DIRECTION OUTPUT ;
    USE SIGNAL ;
    PORT
      LAYER M4 ;
        RECT  0 20.496 0.084 20.52 ;
    END
  END inj_addr_o[117]
  PIN inj_addr_o[118]
    DIRECTION OUTPUT ;
    USE SIGNAL ;
    PORT
      LAYER M4 ;
        RECT  0 20.592 0.084 20.616 ;
    END
  END inj_addr_o[118]
  PIN inj_addr_o[119]
    DIRECTION OUTPUT ;
    USE SIGNAL ;
    PORT
      LAYER M4 ;
        RECT  0 20.688 0.084 20.712 ;
    END
  END inj_addr_o[119]
  PIN inj_addr_o[11]
    DIRECTION OUTPUT ;
    USE SIGNAL ;
    PORT
      LAYER M4 ;
        RECT  0 28.752 0.084 28.776 ;
    END
  END inj_addr_o[11]
  PIN inj_addr_o[120]
    DIRECTION OUTPUT ;
    USE SIGNAL ;
    PORT
      LAYER M4 ;
        RECT  0 20.784 0.084 20.808 ;
    END
  END inj_addr_o[120]
  PIN inj_addr_o[121]
    DIRECTION OUTPUT ;
    USE SIGNAL ;
    PORT
      LAYER M4 ;
        RECT  0 20.88 0.084 20.904 ;
    END
  END inj_addr_o[121]
  PIN inj_addr_o[122]
    DIRECTION OUTPUT ;
    USE SIGNAL ;
    PORT
      LAYER M4 ;
        RECT  0 20.976 0.084 21 ;
    END
  END inj_addr_o[122]
  PIN inj_addr_o[123]
    DIRECTION OUTPUT ;
    USE SIGNAL ;
    PORT
      LAYER M4 ;
        RECT  0 21.072 0.084 21.096 ;
    END
  END inj_addr_o[123]
  PIN inj_addr_o[124]
    DIRECTION OUTPUT ;
    USE SIGNAL ;
    PORT
      LAYER M4 ;
        RECT  0 21.168 0.084 21.192 ;
    END
  END inj_addr_o[124]
  PIN inj_addr_o[125]
    DIRECTION OUTPUT ;
    USE SIGNAL ;
    PORT
      LAYER M4 ;
        RECT  0 21.264 0.084 21.288 ;
    END
  END inj_addr_o[125]
  PIN inj_addr_o[126]
    DIRECTION OUTPUT ;
    USE SIGNAL ;
    PORT
      LAYER M4 ;
        RECT  0 21.36 0.084 21.384 ;
    END
  END inj_addr_o[126]
  PIN inj_addr_o[127]
    DIRECTION OUTPUT ;
    USE SIGNAL ;
    PORT
      LAYER M4 ;
        RECT  0 21.456 0.084 21.48 ;
    END
  END inj_addr_o[127]
  PIN inj_addr_o[128]
    DIRECTION OUTPUT ;
    USE SIGNAL ;
    PORT
      LAYER M4 ;
        RECT  0 24.624 0.084 24.648 ;
    END
  END inj_addr_o[128]
  PIN inj_addr_o[129]
    DIRECTION OUTPUT ;
    USE SIGNAL ;
    PORT
      LAYER M4 ;
        RECT  0 24.72 0.084 24.744 ;
    END
  END inj_addr_o[129]
  PIN inj_addr_o[12]
    DIRECTION OUTPUT ;
    USE SIGNAL ;
    PORT
      LAYER M4 ;
        RECT  0 28.848 0.084 28.872 ;
    END
  END inj_addr_o[12]
  PIN inj_addr_o[130]
    DIRECTION OUTPUT ;
    USE SIGNAL ;
    PORT
      LAYER M4 ;
        RECT  0 24.816 0.084 24.84 ;
    END
  END inj_addr_o[130]
  PIN inj_addr_o[131]
    DIRECTION OUTPUT ;
    USE SIGNAL ;
    PORT
      LAYER M4 ;
        RECT  0 24.912 0.084 24.936 ;
    END
  END inj_addr_o[131]
  PIN inj_addr_o[132]
    DIRECTION OUTPUT ;
    USE SIGNAL ;
    PORT
      LAYER M4 ;
        RECT  0 25.008 0.084 25.032 ;
    END
  END inj_addr_o[132]
  PIN inj_addr_o[133]
    DIRECTION OUTPUT ;
    USE SIGNAL ;
    PORT
      LAYER M4 ;
        RECT  0 25.104 0.084 25.128 ;
    END
  END inj_addr_o[133]
  PIN inj_addr_o[134]
    DIRECTION OUTPUT ;
    USE SIGNAL ;
    PORT
      LAYER M4 ;
        RECT  0 25.2 0.084 25.224 ;
    END
  END inj_addr_o[134]
  PIN inj_addr_o[135]
    DIRECTION OUTPUT ;
    USE SIGNAL ;
    PORT
      LAYER M4 ;
        RECT  0 25.296 0.084 25.32 ;
    END
  END inj_addr_o[135]
  PIN inj_addr_o[136]
    DIRECTION OUTPUT ;
    USE SIGNAL ;
    PORT
      LAYER M4 ;
        RECT  0 25.392 0.084 25.416 ;
    END
  END inj_addr_o[136]
  PIN inj_addr_o[137]
    DIRECTION OUTPUT ;
    USE SIGNAL ;
    PORT
      LAYER M4 ;
        RECT  0 25.488 0.084 25.512 ;
    END
  END inj_addr_o[137]
  PIN inj_addr_o[138]
    DIRECTION OUTPUT ;
    USE SIGNAL ;
    PORT
      LAYER M4 ;
        RECT  0 25.584 0.084 25.608 ;
    END
  END inj_addr_o[138]
  PIN inj_addr_o[139]
    DIRECTION OUTPUT ;
    USE SIGNAL ;
    PORT
      LAYER M4 ;
        RECT  0 25.68 0.084 25.704 ;
    END
  END inj_addr_o[139]
  PIN inj_addr_o[13]
    DIRECTION OUTPUT ;
    USE SIGNAL ;
    PORT
      LAYER M4 ;
        RECT  0 28.944 0.084 28.968 ;
    END
  END inj_addr_o[13]
  PIN inj_addr_o[140]
    DIRECTION OUTPUT ;
    USE SIGNAL ;
    PORT
      LAYER M4 ;
        RECT  0 25.776 0.084 25.8 ;
    END
  END inj_addr_o[140]
  PIN inj_addr_o[141]
    DIRECTION OUTPUT ;
    USE SIGNAL ;
    PORT
      LAYER M4 ;
        RECT  0 25.872 0.084 25.896 ;
    END
  END inj_addr_o[141]
  PIN inj_addr_o[142]
    DIRECTION OUTPUT ;
    USE SIGNAL ;
    PORT
      LAYER M4 ;
        RECT  0 25.968 0.084 25.992 ;
    END
  END inj_addr_o[142]
  PIN inj_addr_o[143]
    DIRECTION OUTPUT ;
    USE SIGNAL ;
    PORT
      LAYER M4 ;
        RECT  0 26.064 0.084 26.088 ;
    END
  END inj_addr_o[143]
  PIN inj_addr_o[144]
    DIRECTION OUTPUT ;
    USE SIGNAL ;
    PORT
      LAYER M4 ;
        RECT  0 26.16 0.084 26.184 ;
    END
  END inj_addr_o[144]
  PIN inj_addr_o[145]
    DIRECTION OUTPUT ;
    USE SIGNAL ;
    PORT
      LAYER M4 ;
        RECT  0 26.256 0.084 26.28 ;
    END
  END inj_addr_o[145]
  PIN inj_addr_o[146]
    DIRECTION OUTPUT ;
    USE SIGNAL ;
    PORT
      LAYER M4 ;
        RECT  0 26.352 0.084 26.376 ;
    END
  END inj_addr_o[146]
  PIN inj_addr_o[147]
    DIRECTION OUTPUT ;
    USE SIGNAL ;
    PORT
      LAYER M4 ;
        RECT  0 26.448 0.084 26.472 ;
    END
  END inj_addr_o[147]
  PIN inj_addr_o[148]
    DIRECTION OUTPUT ;
    USE SIGNAL ;
    PORT
      LAYER M4 ;
        RECT  0 26.544 0.084 26.568 ;
    END
  END inj_addr_o[148]
  PIN inj_addr_o[149]
    DIRECTION OUTPUT ;
    USE SIGNAL ;
    PORT
      LAYER M4 ;
        RECT  0 26.64 0.084 26.664 ;
    END
  END inj_addr_o[149]
  PIN inj_addr_o[14]
    DIRECTION OUTPUT ;
    USE SIGNAL ;
    PORT
      LAYER M4 ;
        RECT  0 29.04 0.084 29.064 ;
    END
  END inj_addr_o[14]
  PIN inj_addr_o[150]
    DIRECTION OUTPUT ;
    USE SIGNAL ;
    PORT
      LAYER M4 ;
        RECT  0 26.736 0.084 26.76 ;
    END
  END inj_addr_o[150]
  PIN inj_addr_o[151]
    DIRECTION OUTPUT ;
    USE SIGNAL ;
    PORT
      LAYER M4 ;
        RECT  0 26.832 0.084 26.856 ;
    END
  END inj_addr_o[151]
  PIN inj_addr_o[152]
    DIRECTION OUTPUT ;
    USE SIGNAL ;
    PORT
      LAYER M4 ;
        RECT  0 26.928 0.084 26.952 ;
    END
  END inj_addr_o[152]
  PIN inj_addr_o[153]
    DIRECTION OUTPUT ;
    USE SIGNAL ;
    PORT
      LAYER M4 ;
        RECT  0 27.024 0.084 27.048 ;
    END
  END inj_addr_o[153]
  PIN inj_addr_o[154]
    DIRECTION OUTPUT ;
    USE SIGNAL ;
    PORT
      LAYER M4 ;
        RECT  0 27.12 0.084 27.144 ;
    END
  END inj_addr_o[154]
  PIN inj_addr_o[155]
    DIRECTION OUTPUT ;
    USE SIGNAL ;
    PORT
      LAYER M4 ;
        RECT  0 27.216 0.084 27.24 ;
    END
  END inj_addr_o[155]
  PIN inj_addr_o[156]
    DIRECTION OUTPUT ;
    USE SIGNAL ;
    PORT
      LAYER M4 ;
        RECT  0 27.312 0.084 27.336 ;
    END
  END inj_addr_o[156]
  PIN inj_addr_o[157]
    DIRECTION OUTPUT ;
    USE SIGNAL ;
    PORT
      LAYER M4 ;
        RECT  0 27.408 0.084 27.432 ;
    END
  END inj_addr_o[157]
  PIN inj_addr_o[158]
    DIRECTION OUTPUT ;
    USE SIGNAL ;
    PORT
      LAYER M4 ;
        RECT  0 27.504 0.084 27.528 ;
    END
  END inj_addr_o[158]
  PIN inj_addr_o[159]
    DIRECTION OUTPUT ;
    USE SIGNAL ;
    PORT
      LAYER M4 ;
        RECT  0 27.6 0.084 27.624 ;
    END
  END inj_addr_o[159]
  PIN inj_addr_o[15]
    DIRECTION OUTPUT ;
    USE SIGNAL ;
    PORT
      LAYER M4 ;
        RECT  0 29.136 0.084 29.16 ;
    END
  END inj_addr_o[15]
  PIN inj_addr_o[16]
    DIRECTION OUTPUT ;
    USE SIGNAL ;
    PORT
      LAYER M4 ;
        RECT  0 29.232 0.084 29.256 ;
    END
  END inj_addr_o[16]
  PIN inj_addr_o[17]
    DIRECTION OUTPUT ;
    USE SIGNAL ;
    PORT
      LAYER M4 ;
        RECT  0 29.328 0.084 29.352 ;
    END
  END inj_addr_o[17]
  PIN inj_addr_o[18]
    DIRECTION OUTPUT ;
    USE SIGNAL ;
    PORT
      LAYER M4 ;
        RECT  0 29.424 0.084 29.448 ;
    END
  END inj_addr_o[18]
  PIN inj_addr_o[19]
    DIRECTION OUTPUT ;
    USE SIGNAL ;
    PORT
      LAYER M4 ;
        RECT  0 29.52 0.084 29.544 ;
    END
  END inj_addr_o[19]
  PIN inj_addr_o[1]
    DIRECTION OUTPUT ;
    USE SIGNAL ;
    PORT
      LAYER M4 ;
        RECT  0 27.792 0.084 27.816 ;
    END
  END inj_addr_o[1]
  PIN inj_addr_o[20]
    DIRECTION OUTPUT ;
    USE SIGNAL ;
    PORT
      LAYER M4 ;
        RECT  0 29.616 0.084 29.64 ;
    END
  END inj_addr_o[20]
  PIN inj_addr_o[21]
    DIRECTION OUTPUT ;
    USE SIGNAL ;
    PORT
      LAYER M4 ;
        RECT  0 29.712 0.084 29.736 ;
    END
  END inj_addr_o[21]
  PIN inj_addr_o[22]
    DIRECTION OUTPUT ;
    USE SIGNAL ;
    PORT
      LAYER M4 ;
        RECT  0 29.808 0.084 29.832 ;
    END
  END inj_addr_o[22]
  PIN inj_addr_o[23]
    DIRECTION OUTPUT ;
    USE SIGNAL ;
    PORT
      LAYER M4 ;
        RECT  0 29.904 0.084 29.928 ;
    END
  END inj_addr_o[23]
  PIN inj_addr_o[24]
    DIRECTION OUTPUT ;
    USE SIGNAL ;
    PORT
      LAYER M4 ;
        RECT  0 30 0.084 30.024 ;
    END
  END inj_addr_o[24]
  PIN inj_addr_o[25]
    DIRECTION OUTPUT ;
    USE SIGNAL ;
    PORT
      LAYER M4 ;
        RECT  0 30.096 0.084 30.12 ;
    END
  END inj_addr_o[25]
  PIN inj_addr_o[26]
    DIRECTION OUTPUT ;
    USE SIGNAL ;
    PORT
      LAYER M4 ;
        RECT  0 30.192 0.084 30.216 ;
    END
  END inj_addr_o[26]
  PIN inj_addr_o[27]
    DIRECTION OUTPUT ;
    USE SIGNAL ;
    PORT
      LAYER M4 ;
        RECT  0 30.288 0.084 30.312 ;
    END
  END inj_addr_o[27]
  PIN inj_addr_o[28]
    DIRECTION OUTPUT ;
    USE SIGNAL ;
    PORT
      LAYER M4 ;
        RECT  0 30.384 0.084 30.408 ;
    END
  END inj_addr_o[28]
  PIN inj_addr_o[29]
    DIRECTION OUTPUT ;
    USE SIGNAL ;
    PORT
      LAYER M4 ;
        RECT  0 30.48 0.084 30.504 ;
    END
  END inj_addr_o[29]
  PIN inj_addr_o[2]
    DIRECTION OUTPUT ;
    USE SIGNAL ;
    PORT
      LAYER M4 ;
        RECT  0 27.888 0.084 27.912 ;
    END
  END inj_addr_o[2]
  PIN inj_addr_o[30]
    DIRECTION OUTPUT ;
    USE SIGNAL ;
    PORT
      LAYER M4 ;
        RECT  0 30.576 0.084 30.6 ;
    END
  END inj_addr_o[30]
  PIN inj_addr_o[31]
    DIRECTION OUTPUT ;
    USE SIGNAL ;
    PORT
      LAYER M4 ;
        RECT  0 30.672 0.084 30.696 ;
    END
  END inj_addr_o[31]
  PIN inj_addr_o[32]
    DIRECTION OUTPUT ;
    USE SIGNAL ;
    PORT
      LAYER M4 ;
        RECT  0 15.408 0.084 15.432 ;
    END
  END inj_addr_o[32]
  PIN inj_addr_o[33]
    DIRECTION OUTPUT ;
    USE SIGNAL ;
    PORT
      LAYER M4 ;
        RECT  0 15.504 0.084 15.528 ;
    END
  END inj_addr_o[33]
  PIN inj_addr_o[34]
    DIRECTION OUTPUT ;
    USE SIGNAL ;
    PORT
      LAYER M4 ;
        RECT  0 15.6 0.084 15.624 ;
    END
  END inj_addr_o[34]
  PIN inj_addr_o[35]
    DIRECTION OUTPUT ;
    USE SIGNAL ;
    PORT
      LAYER M4 ;
        RECT  0 15.696 0.084 15.72 ;
    END
  END inj_addr_o[35]
  PIN inj_addr_o[36]
    DIRECTION OUTPUT ;
    USE SIGNAL ;
    PORT
      LAYER M4 ;
        RECT  0 15.792 0.084 15.816 ;
    END
  END inj_addr_o[36]
  PIN inj_addr_o[37]
    DIRECTION OUTPUT ;
    USE SIGNAL ;
    PORT
      LAYER M4 ;
        RECT  0 15.888 0.084 15.912 ;
    END
  END inj_addr_o[37]
  PIN inj_addr_o[38]
    DIRECTION OUTPUT ;
    USE SIGNAL ;
    PORT
      LAYER M4 ;
        RECT  0 15.984 0.084 16.008 ;
    END
  END inj_addr_o[38]
  PIN inj_addr_o[39]
    DIRECTION OUTPUT ;
    USE SIGNAL ;
    PORT
      LAYER M4 ;
        RECT  0 16.08 0.084 16.104 ;
    END
  END inj_addr_o[39]
  PIN inj_addr_o[3]
    DIRECTION OUTPUT ;
    USE SIGNAL ;
    PORT
      LAYER M4 ;
        RECT  0 27.984 0.084 28.008 ;
    END
  END inj_addr_o[3]
  PIN inj_addr_o[40]
    DIRECTION OUTPUT ;
    USE SIGNAL ;
    PORT
      LAYER M4 ;
        RECT  0 16.176 0.084 16.2 ;
    END
  END inj_addr_o[40]
  PIN inj_addr_o[41]
    DIRECTION OUTPUT ;
    USE SIGNAL ;
    PORT
      LAYER M4 ;
        RECT  0 16.272 0.084 16.296 ;
    END
  END inj_addr_o[41]
  PIN inj_addr_o[42]
    DIRECTION OUTPUT ;
    USE SIGNAL ;
    PORT
      LAYER M4 ;
        RECT  0 16.368 0.084 16.392 ;
    END
  END inj_addr_o[42]
  PIN inj_addr_o[43]
    DIRECTION OUTPUT ;
    USE SIGNAL ;
    PORT
      LAYER M4 ;
        RECT  0 16.464 0.084 16.488 ;
    END
  END inj_addr_o[43]
  PIN inj_addr_o[44]
    DIRECTION OUTPUT ;
    USE SIGNAL ;
    PORT
      LAYER M4 ;
        RECT  0 16.56 0.084 16.584 ;
    END
  END inj_addr_o[44]
  PIN inj_addr_o[45]
    DIRECTION OUTPUT ;
    USE SIGNAL ;
    PORT
      LAYER M4 ;
        RECT  0 16.656 0.084 16.68 ;
    END
  END inj_addr_o[45]
  PIN inj_addr_o[46]
    DIRECTION OUTPUT ;
    USE SIGNAL ;
    PORT
      LAYER M4 ;
        RECT  0 16.752 0.084 16.776 ;
    END
  END inj_addr_o[46]
  PIN inj_addr_o[47]
    DIRECTION OUTPUT ;
    USE SIGNAL ;
    PORT
      LAYER M4 ;
        RECT  0 16.848 0.084 16.872 ;
    END
  END inj_addr_o[47]
  PIN inj_addr_o[48]
    DIRECTION OUTPUT ;
    USE SIGNAL ;
    PORT
      LAYER M4 ;
        RECT  0 16.944 0.084 16.968 ;
    END
  END inj_addr_o[48]
  PIN inj_addr_o[49]
    DIRECTION OUTPUT ;
    USE SIGNAL ;
    PORT
      LAYER M4 ;
        RECT  0 17.04 0.084 17.064 ;
    END
  END inj_addr_o[49]
  PIN inj_addr_o[4]
    DIRECTION OUTPUT ;
    USE SIGNAL ;
    PORT
      LAYER M4 ;
        RECT  0 28.08 0.084 28.104 ;
    END
  END inj_addr_o[4]
  PIN inj_addr_o[50]
    DIRECTION OUTPUT ;
    USE SIGNAL ;
    PORT
      LAYER M4 ;
        RECT  0 17.136 0.084 17.16 ;
    END
  END inj_addr_o[50]
  PIN inj_addr_o[51]
    DIRECTION OUTPUT ;
    USE SIGNAL ;
    PORT
      LAYER M4 ;
        RECT  0 17.232 0.084 17.256 ;
    END
  END inj_addr_o[51]
  PIN inj_addr_o[52]
    DIRECTION OUTPUT ;
    USE SIGNAL ;
    PORT
      LAYER M4 ;
        RECT  0 17.328 0.084 17.352 ;
    END
  END inj_addr_o[52]
  PIN inj_addr_o[53]
    DIRECTION OUTPUT ;
    USE SIGNAL ;
    PORT
      LAYER M4 ;
        RECT  0 17.424 0.084 17.448 ;
    END
  END inj_addr_o[53]
  PIN inj_addr_o[54]
    DIRECTION OUTPUT ;
    USE SIGNAL ;
    PORT
      LAYER M4 ;
        RECT  0 17.52 0.084 17.544 ;
    END
  END inj_addr_o[54]
  PIN inj_addr_o[55]
    DIRECTION OUTPUT ;
    USE SIGNAL ;
    PORT
      LAYER M4 ;
        RECT  0 17.616 0.084 17.64 ;
    END
  END inj_addr_o[55]
  PIN inj_addr_o[56]
    DIRECTION OUTPUT ;
    USE SIGNAL ;
    PORT
      LAYER M4 ;
        RECT  0 17.712 0.084 17.736 ;
    END
  END inj_addr_o[56]
  PIN inj_addr_o[57]
    DIRECTION OUTPUT ;
    USE SIGNAL ;
    PORT
      LAYER M4 ;
        RECT  0 17.808 0.084 17.832 ;
    END
  END inj_addr_o[57]
  PIN inj_addr_o[58]
    DIRECTION OUTPUT ;
    USE SIGNAL ;
    PORT
      LAYER M4 ;
        RECT  0 17.904 0.084 17.928 ;
    END
  END inj_addr_o[58]
  PIN inj_addr_o[59]
    DIRECTION OUTPUT ;
    USE SIGNAL ;
    PORT
      LAYER M4 ;
        RECT  0 18 0.084 18.024 ;
    END
  END inj_addr_o[59]
  PIN inj_addr_o[5]
    DIRECTION OUTPUT ;
    USE SIGNAL ;
    PORT
      LAYER M4 ;
        RECT  0 28.176 0.084 28.2 ;
    END
  END inj_addr_o[5]
  PIN inj_addr_o[60]
    DIRECTION OUTPUT ;
    USE SIGNAL ;
    PORT
      LAYER M4 ;
        RECT  0 18.096 0.084 18.12 ;
    END
  END inj_addr_o[60]
  PIN inj_addr_o[61]
    DIRECTION OUTPUT ;
    USE SIGNAL ;
    PORT
      LAYER M4 ;
        RECT  0 18.192 0.084 18.216 ;
    END
  END inj_addr_o[61]
  PIN inj_addr_o[62]
    DIRECTION OUTPUT ;
    USE SIGNAL ;
    PORT
      LAYER M4 ;
        RECT  0 18.288 0.084 18.312 ;
    END
  END inj_addr_o[62]
  PIN inj_addr_o[63]
    DIRECTION OUTPUT ;
    USE SIGNAL ;
    PORT
      LAYER M4 ;
        RECT  0 18.384 0.084 18.408 ;
    END
  END inj_addr_o[63]
  PIN inj_addr_o[64]
    DIRECTION OUTPUT ;
    USE SIGNAL ;
    PORT
      LAYER M4 ;
        RECT  0 21.552 0.084 21.576 ;
    END
  END inj_addr_o[64]
  PIN inj_addr_o[65]
    DIRECTION OUTPUT ;
    USE SIGNAL ;
    PORT
      LAYER M4 ;
        RECT  0 21.648 0.084 21.672 ;
    END
  END inj_addr_o[65]
  PIN inj_addr_o[66]
    DIRECTION OUTPUT ;
    USE SIGNAL ;
    PORT
      LAYER M4 ;
        RECT  0 21.744 0.084 21.768 ;
    END
  END inj_addr_o[66]
  PIN inj_addr_o[67]
    DIRECTION OUTPUT ;
    USE SIGNAL ;
    PORT
      LAYER M4 ;
        RECT  0 21.84 0.084 21.864 ;
    END
  END inj_addr_o[67]
  PIN inj_addr_o[68]
    DIRECTION OUTPUT ;
    USE SIGNAL ;
    PORT
      LAYER M4 ;
        RECT  0 21.936 0.084 21.96 ;
    END
  END inj_addr_o[68]
  PIN inj_addr_o[69]
    DIRECTION OUTPUT ;
    USE SIGNAL ;
    PORT
      LAYER M4 ;
        RECT  0 22.032 0.084 22.056 ;
    END
  END inj_addr_o[69]
  PIN inj_addr_o[6]
    DIRECTION OUTPUT ;
    USE SIGNAL ;
    PORT
      LAYER M4 ;
        RECT  0 28.272 0.084 28.296 ;
    END
  END inj_addr_o[6]
  PIN inj_addr_o[70]
    DIRECTION OUTPUT ;
    USE SIGNAL ;
    PORT
      LAYER M4 ;
        RECT  0 22.128 0.084 22.152 ;
    END
  END inj_addr_o[70]
  PIN inj_addr_o[71]
    DIRECTION OUTPUT ;
    USE SIGNAL ;
    PORT
      LAYER M4 ;
        RECT  0 22.224 0.084 22.248 ;
    END
  END inj_addr_o[71]
  PIN inj_addr_o[72]
    DIRECTION OUTPUT ;
    USE SIGNAL ;
    PORT
      LAYER M4 ;
        RECT  0 22.32 0.084 22.344 ;
    END
  END inj_addr_o[72]
  PIN inj_addr_o[73]
    DIRECTION OUTPUT ;
    USE SIGNAL ;
    PORT
      LAYER M4 ;
        RECT  0 22.416 0.084 22.44 ;
    END
  END inj_addr_o[73]
  PIN inj_addr_o[74]
    DIRECTION OUTPUT ;
    USE SIGNAL ;
    PORT
      LAYER M4 ;
        RECT  0 22.512 0.084 22.536 ;
    END
  END inj_addr_o[74]
  PIN inj_addr_o[75]
    DIRECTION OUTPUT ;
    USE SIGNAL ;
    PORT
      LAYER M4 ;
        RECT  0 22.608 0.084 22.632 ;
    END
  END inj_addr_o[75]
  PIN inj_addr_o[76]
    DIRECTION OUTPUT ;
    USE SIGNAL ;
    PORT
      LAYER M4 ;
        RECT  0 22.704 0.084 22.728 ;
    END
  END inj_addr_o[76]
  PIN inj_addr_o[77]
    DIRECTION OUTPUT ;
    USE SIGNAL ;
    PORT
      LAYER M4 ;
        RECT  0 22.8 0.084 22.824 ;
    END
  END inj_addr_o[77]
  PIN inj_addr_o[78]
    DIRECTION OUTPUT ;
    USE SIGNAL ;
    PORT
      LAYER M4 ;
        RECT  0 22.896 0.084 22.92 ;
    END
  END inj_addr_o[78]
  PIN inj_addr_o[79]
    DIRECTION OUTPUT ;
    USE SIGNAL ;
    PORT
      LAYER M4 ;
        RECT  0 22.992 0.084 23.016 ;
    END
  END inj_addr_o[79]
  PIN inj_addr_o[7]
    DIRECTION OUTPUT ;
    USE SIGNAL ;
    PORT
      LAYER M4 ;
        RECT  0 28.368 0.084 28.392 ;
    END
  END inj_addr_o[7]
  PIN inj_addr_o[80]
    DIRECTION OUTPUT ;
    USE SIGNAL ;
    PORT
      LAYER M4 ;
        RECT  0 23.088 0.084 23.112 ;
    END
  END inj_addr_o[80]
  PIN inj_addr_o[81]
    DIRECTION OUTPUT ;
    USE SIGNAL ;
    PORT
      LAYER M4 ;
        RECT  0 23.184 0.084 23.208 ;
    END
  END inj_addr_o[81]
  PIN inj_addr_o[82]
    DIRECTION OUTPUT ;
    USE SIGNAL ;
    PORT
      LAYER M4 ;
        RECT  0 23.28 0.084 23.304 ;
    END
  END inj_addr_o[82]
  PIN inj_addr_o[83]
    DIRECTION OUTPUT ;
    USE SIGNAL ;
    PORT
      LAYER M4 ;
        RECT  0 23.376 0.084 23.4 ;
    END
  END inj_addr_o[83]
  PIN inj_addr_o[84]
    DIRECTION OUTPUT ;
    USE SIGNAL ;
    PORT
      LAYER M4 ;
        RECT  0 23.472 0.084 23.496 ;
    END
  END inj_addr_o[84]
  PIN inj_addr_o[85]
    DIRECTION OUTPUT ;
    USE SIGNAL ;
    PORT
      LAYER M4 ;
        RECT  0 23.568 0.084 23.592 ;
    END
  END inj_addr_o[85]
  PIN inj_addr_o[86]
    DIRECTION OUTPUT ;
    USE SIGNAL ;
    PORT
      LAYER M4 ;
        RECT  0 23.664 0.084 23.688 ;
    END
  END inj_addr_o[86]
  PIN inj_addr_o[87]
    DIRECTION OUTPUT ;
    USE SIGNAL ;
    PORT
      LAYER M4 ;
        RECT  0 23.76 0.084 23.784 ;
    END
  END inj_addr_o[87]
  PIN inj_addr_o[88]
    DIRECTION OUTPUT ;
    USE SIGNAL ;
    PORT
      LAYER M4 ;
        RECT  0 23.856 0.084 23.88 ;
    END
  END inj_addr_o[88]
  PIN inj_addr_o[89]
    DIRECTION OUTPUT ;
    USE SIGNAL ;
    PORT
      LAYER M4 ;
        RECT  0 23.952 0.084 23.976 ;
    END
  END inj_addr_o[89]
  PIN inj_addr_o[8]
    DIRECTION OUTPUT ;
    USE SIGNAL ;
    PORT
      LAYER M4 ;
        RECT  0 28.464 0.084 28.488 ;
    END
  END inj_addr_o[8]
  PIN inj_addr_o[90]
    DIRECTION OUTPUT ;
    USE SIGNAL ;
    PORT
      LAYER M4 ;
        RECT  0 24.048 0.084 24.072 ;
    END
  END inj_addr_o[90]
  PIN inj_addr_o[91]
    DIRECTION OUTPUT ;
    USE SIGNAL ;
    PORT
      LAYER M4 ;
        RECT  0 24.144 0.084 24.168 ;
    END
  END inj_addr_o[91]
  PIN inj_addr_o[92]
    DIRECTION OUTPUT ;
    USE SIGNAL ;
    PORT
      LAYER M4 ;
        RECT  0 24.24 0.084 24.264 ;
    END
  END inj_addr_o[92]
  PIN inj_addr_o[93]
    DIRECTION OUTPUT ;
    USE SIGNAL ;
    PORT
      LAYER M4 ;
        RECT  0 24.336 0.084 24.36 ;
    END
  END inj_addr_o[93]
  PIN inj_addr_o[94]
    DIRECTION OUTPUT ;
    USE SIGNAL ;
    PORT
      LAYER M4 ;
        RECT  0 24.432 0.084 24.456 ;
    END
  END inj_addr_o[94]
  PIN inj_addr_o[95]
    DIRECTION OUTPUT ;
    USE SIGNAL ;
    PORT
      LAYER M4 ;
        RECT  0 24.528 0.084 24.552 ;
    END
  END inj_addr_o[95]
  PIN inj_addr_o[96]
    DIRECTION OUTPUT ;
    USE SIGNAL ;
    PORT
      LAYER M4 ;
        RECT  0 18.48 0.084 18.504 ;
    END
  END inj_addr_o[96]
  PIN inj_addr_o[97]
    DIRECTION OUTPUT ;
    USE SIGNAL ;
    PORT
      LAYER M4 ;
        RECT  0 18.576 0.084 18.6 ;
    END
  END inj_addr_o[97]
  PIN inj_addr_o[98]
    DIRECTION OUTPUT ;
    USE SIGNAL ;
    PORT
      LAYER M4 ;
        RECT  0 18.672 0.084 18.696 ;
    END
  END inj_addr_o[98]
  PIN inj_addr_o[99]
    DIRECTION OUTPUT ;
    USE SIGNAL ;
    PORT
      LAYER M4 ;
        RECT  0 18.768 0.084 18.792 ;
    END
  END inj_addr_o[99]
  PIN inj_addr_o[9]
    DIRECTION OUTPUT ;
    USE SIGNAL ;
    PORT
      LAYER M4 ;
        RECT  0 28.56 0.084 28.584 ;
    END
  END inj_addr_o[9]
  PIN inj_rd_i[0]
    DIRECTION INPUT ;
    USE SIGNAL ;
    PORT
      LAYER M4 ;
        RECT  34.476 19.152 34.56 19.176 ;
    END
  END inj_rd_i[0]
  PIN inj_rd_i[1]
    DIRECTION INPUT ;
    USE SIGNAL ;
    PORT
      LAYER M4 ;
        RECT  34.476 19.248 34.56 19.272 ;
    END
  END inj_rd_i[1]
  PIN inj_rd_o[0]
    DIRECTION OUTPUT ;
    USE SIGNAL ;
    PORT
      LAYER M4 ;
        RECT  0 15.216 0.084 15.24 ;
    END
  END inj_rd_o[0]
  PIN inj_rd_o[1]
    DIRECTION OUTPUT ;
    USE SIGNAL ;
    PORT
      LAYER M4 ;
        RECT  0 15.312 0.084 15.336 ;
    END
  END inj_rd_o[1]
  PIN rst_n
    DIRECTION INPUT ;
    USE SIGNAL ;
    PORT
      LAYER M5 ;
        RECT  18 34.476 18.024 34.56 ;
    END
  END rst_n
  PIN VDD
    DIRECTION INOUT ;
    USE POWER ;
    PORT
      LAYER M5 ;
        RECT  32.292 2.151 32.412 32.409 ;
        RECT  29.592 2.151 29.712 32.409 ;
        RECT  26.892 2.151 27.012 32.409 ;
        RECT  24.192 2.151 24.312 32.409 ;
        RECT  21.492 2.151 21.612 32.409 ;
        RECT  18.792 2.151 18.912 32.409 ;
        RECT  16.092 2.151 16.212 32.409 ;
        RECT  13.392 2.151 13.512 32.409 ;
        RECT  10.692 2.151 10.812 32.409 ;
        RECT  7.992 2.151 8.112 32.409 ;
        RECT  5.292 2.151 5.412 32.409 ;
        RECT  2.592 2.151 2.712 32.409 ;
    END
  END VDD
  PIN VSS
    DIRECTION INOUT ;
    USE GROUND ;
    PORT
      LAYER M5 ;
        RECT  32.1 2.137 32.22 32.423 ;
        RECT  29.4 2.137 29.52 32.423 ;
        RECT  26.7 2.137 26.82 32.423 ;
        RECT  24 2.137 24.12 32.423 ;
        RECT  21.3 2.137 21.42 32.423 ;
        RECT  18.6 2.137 18.72 32.423 ;
        RECT  15.9 2.137 16.02 32.423 ;
        RECT  13.2 2.137 13.32 32.423 ;
        RECT  10.5 2.137 10.62 32.423 ;
        RECT  7.8 2.137 7.92 32.423 ;
        RECT  5.1 2.137 5.22 32.423 ;
        RECT  2.4 2.137 2.52 32.423 ;
    END
  END VSS
  OBS
    LAYER RVTN ;
     RECT  2.16 2.16 32.4 2.295 ;
     RECT  2.16 2.565 32.4 2.835 ;
     RECT  2.16 3.105 32.4 3.375 ;
     RECT  2.16 3.645 32.4 3.915 ;
     RECT  2.16 4.185 32.4 4.455 ;
     RECT  2.16 4.725 32.4 4.995 ;
     RECT  2.16 5.265 32.4 5.535 ;
     RECT  2.16 5.805 32.4 6.075 ;
     RECT  2.16 6.345 32.4 6.615 ;
     RECT  2.16 6.885 32.4 7.155 ;
     RECT  2.16 7.425 32.4 7.695 ;
     RECT  2.16 7.965 32.4 8.235 ;
     RECT  2.16 8.505 32.4 8.775 ;
     RECT  2.16 9.045 32.4 9.315 ;
     RECT  2.16 9.585 32.4 9.855 ;
     RECT  2.16 10.125 32.4 10.395 ;
     RECT  2.16 10.665 32.4 10.935 ;
     RECT  2.16 11.205 32.4 11.475 ;
     RECT  2.16 11.745 32.4 12.015 ;
     RECT  2.16 12.285 32.4 12.555 ;
     RECT  2.16 12.825 32.4 13.095 ;
     RECT  2.16 13.365 32.4 13.635 ;
     RECT  2.16 13.905 32.4 14.175 ;
     RECT  2.16 14.445 32.4 14.715 ;
     RECT  2.16 14.985 32.4 15.255 ;
     RECT  2.16 15.525 32.4 15.795 ;
     RECT  2.16 16.065 32.4 16.335 ;
     RECT  2.16 16.605 32.4 16.875 ;
     RECT  2.16 17.145 32.4 17.415 ;
     RECT  2.16 17.685 32.4 17.955 ;
     RECT  2.16 18.225 32.4 18.495 ;
     RECT  2.16 18.765 32.4 19.035 ;
     RECT  2.16 19.305 32.4 19.575 ;
     RECT  2.16 19.845 32.4 20.115 ;
     RECT  2.16 20.385 32.4 20.655 ;
     RECT  2.16 20.925 32.4 21.195 ;
     RECT  2.16 21.465 32.4 21.735 ;
     RECT  2.16 22.005 32.4 22.275 ;
     RECT  2.16 22.545 32.4 22.815 ;
     RECT  2.16 23.085 32.4 23.355 ;
     RECT  2.16 23.625 32.4 23.895 ;
     RECT  2.16 24.165 32.4 24.435 ;
     RECT  2.16 24.705 32.4 24.975 ;
     RECT  2.16 25.245 32.4 25.515 ;
     RECT  2.16 25.785 32.4 26.055 ;
     RECT  2.16 26.325 32.4 26.595 ;
     RECT  2.16 26.865 32.4 27.135 ;
     RECT  2.16 27.405 32.4 27.675 ;
     RECT  2.16 27.945 32.4 28.215 ;
     RECT  2.16 28.485 32.4 28.755 ;
     RECT  2.16 29.025 32.4 29.295 ;
     RECT  2.16 29.565 32.4 29.835 ;
     RECT  2.16 30.105 32.4 30.375 ;
     RECT  2.16 30.645 32.4 30.915 ;
     RECT  2.16 31.185 32.4 31.455 ;
     RECT  2.16 31.725 32.4 31.995 ;
     RECT  2.16 32.265 32.4 32.4 ;
    LAYER RVTP ;
     RECT  2.16 2.295 32.4 2.565 ;
     RECT  2.16 2.835 32.4 3.105 ;
     RECT  2.16 3.375 32.4 3.645 ;
     RECT  2.16 3.915 32.4 4.185 ;
     RECT  2.16 4.455 32.4 4.725 ;
     RECT  2.16 4.995 32.4 5.265 ;
     RECT  2.16 5.535 32.4 5.805 ;
     RECT  2.16 6.075 32.4 6.345 ;
     RECT  2.16 6.615 32.4 6.885 ;
     RECT  2.16 7.155 32.4 7.425 ;
     RECT  2.16 7.695 32.4 7.965 ;
     RECT  2.16 8.235 32.4 8.505 ;
     RECT  2.16 8.775 32.4 9.045 ;
     RECT  2.16 9.315 32.4 9.585 ;
     RECT  2.16 9.855 32.4 10.125 ;
     RECT  2.16 10.395 32.4 10.665 ;
     RECT  2.16 10.935 32.4 11.205 ;
     RECT  2.16 11.475 32.4 11.745 ;
     RECT  2.16 12.015 32.4 12.285 ;
     RECT  2.16 12.555 32.4 12.825 ;
     RECT  2.16 13.095 32.4 13.365 ;
     RECT  2.16 13.635 32.4 13.905 ;
     RECT  2.16 14.175 32.4 14.445 ;
     RECT  2.16 14.715 32.4 14.985 ;
     RECT  2.16 15.255 32.4 15.525 ;
     RECT  2.16 15.795 32.4 16.065 ;
     RECT  2.16 16.335 32.4 16.605 ;
     RECT  2.16 16.875 32.4 17.145 ;
     RECT  2.16 17.415 32.4 17.685 ;
     RECT  2.16 17.955 32.4 18.225 ;
     RECT  2.16 18.495 32.4 18.765 ;
     RECT  2.16 19.035 32.4 19.305 ;
     RECT  2.16 19.575 32.4 19.845 ;
     RECT  2.16 20.115 32.4 20.385 ;
     RECT  2.16 20.655 32.4 20.925 ;
     RECT  2.16 21.195 32.4 21.465 ;
     RECT  2.16 21.735 32.4 22.005 ;
     RECT  2.16 22.275 32.4 22.545 ;
     RECT  2.16 22.815 32.4 23.085 ;
     RECT  2.16 23.355 32.4 23.625 ;
     RECT  2.16 23.895 32.4 24.165 ;
     RECT  2.16 24.435 32.4 24.705 ;
     RECT  2.16 24.975 32.4 25.245 ;
     RECT  2.16 25.515 32.4 25.785 ;
     RECT  2.16 26.055 32.4 26.325 ;
     RECT  2.16 26.595 32.4 26.865 ;
     RECT  2.16 27.135 32.4 27.405 ;
     RECT  2.16 27.675 32.4 27.945 ;
     RECT  2.16 28.215 32.4 28.485 ;
     RECT  2.16 28.755 32.4 29.025 ;
     RECT  2.16 29.295 32.4 29.565 ;
     RECT  2.16 29.835 32.4 30.105 ;
     RECT  2.16 30.375 32.4 30.645 ;
     RECT  2.16 30.915 32.4 31.185 ;
     RECT  2.16 31.455 32.4 31.725 ;
     RECT  2.16 31.995 32.4 32.265 ;
    LAYER M1 ;
     RECT  2.16 2.151 32.4 32.409 ;
    LAYER M2 ;
     RECT  0.067 14.796 0.103 14.814 ;
     RECT  0.067 15.966 0.103 15.984 ;
     RECT  0.103 14.796 0.139 15.984 ;
     RECT  0.103 17.271 0.139 17.289 ;
     RECT  0.103 18.198 0.139 18.216 ;
     RECT  0.103 29.538 0.139 29.556 ;
     RECT  0.139 14.526 0.167 15.984 ;
     RECT  0.103 22.518 0.175 22.806 ;
     RECT  0.139 17.271 0.203 18.216 ;
     RECT  0.103 19.62 0.203 19.638 ;
     RECT  0.103 21.51 0.203 21.528 ;
     RECT  0.175 22.446 0.203 22.806 ;
     RECT  0.103 25.83 0.203 25.848 ;
     RECT  0.103 26.766 0.203 27.468 ;
     RECT  0.203 17.496 0.239 17.514 ;
     RECT  0.203 22.446 0.275 22.644 ;
     RECT  0.203 27.45 0.275 27.468 ;
     RECT  0.211 26.136 0.311 26.154 ;
     RECT  0.139 29.268 0.383 29.556 ;
     RECT  0.103 30.582 0.383 30.6 ;
     RECT  0.283 23.598 0.419 23.616 ;
     RECT  0.499 16.344 0.535 16.362 ;
     RECT  0.383 29.538 0.563 29.556 ;
     RECT  0.167 14.526 1.147 15.354 ;
     RECT  1.147 13.986 1.219 15.354 ;
     RECT  0.535 16.344 1.219 16.434 ;
     RECT  1.219 13.986 2.16 16.434 ;
     RECT  0.535 18.576 2.16 18.594 ;
     RECT  0.275 22.626 2.16 22.644 ;
     RECT  1.291 30.924 2.16 30.942 ;
     RECT  2.16 2.151 32.4 32.409 ;
     RECT  32.4 2.421 32.412 32.139 ;
     RECT  32.412 3.618 32.531 20.178 ;
     RECT  32.531 3.618 32.963 20.106 ;
     RECT  32.963 3.618 33.107 19.638 ;
     RECT  33.107 4.158 33.143 19.638 ;
     RECT  33.143 4.968 33.287 19.638 ;
     RECT  33.287 4.968 33.503 19.368 ;
     RECT  33.143 4.158 33.539 4.176 ;
     RECT  33.503 4.968 33.539 9.576 ;
     RECT  33.503 10.368 33.539 13.896 ;
     RECT  33.503 14.688 33.539 19.368 ;
     RECT  33.539 14.688 33.575 15.084 ;
     RECT  33.539 16.308 33.575 19.368 ;
     RECT  33.539 5.238 33.611 6.714 ;
     RECT  33.539 7.668 33.611 9.342 ;
     RECT  33.575 14.994 33.611 15.084 ;
     RECT  33.575 16.308 33.611 19.296 ;
     RECT  33.611 8.046 33.647 9.036 ;
     RECT  33.539 10.368 33.647 10.728 ;
     RECT  33.539 11.556 33.647 13.662 ;
     RECT  33.611 16.38 33.647 19.296 ;
     RECT  33.611 5.238 33.683 6.408 ;
     RECT  33.647 10.476 33.683 10.656 ;
     RECT  33.683 5.778 34.403 5.796 ;
     RECT  33.647 9.018 34.403 9.036 ;
     RECT  33.683 10.638 34.403 10.656 ;
     RECT  33.647 19.008 34.403 19.296 ;
     RECT  33.647 12.096 34.439 13.662 ;
     RECT  33.611 14.994 34.439 15.048 ;
     RECT  33.647 16.542 34.439 17.712 ;
     RECT  33.647 8.046 34.475 8.064 ;
     RECT  34.439 12.528 34.475 12.546 ;
     RECT  34.439 13.644 34.475 13.662 ;
     RECT  34.439 15.03 34.475 15.048 ;
     RECT  34.439 16.542 34.475 16.56 ;
     RECT  34.439 17.541 34.475 17.559 ;
     RECT  34.403 19.008 34.475 19.026 ;
    LAYER M3 ;
     RECT  2.415 2.143 2.505 2.413 ;
     RECT  5.115 2.143 5.205 2.413 ;
     RECT  7.815 2.143 7.905 2.413 ;
     RECT  10.515 2.143 10.605 2.413 ;
     RECT  13.215 2.143 13.305 2.413 ;
     RECT  15.915 2.143 16.005 2.413 ;
     RECT  18.615 2.143 18.705 2.413 ;
     RECT  21.315 2.143 21.405 2.413 ;
     RECT  24.015 2.143 24.105 2.413 ;
     RECT  26.715 2.143 26.805 2.413 ;
     RECT  29.415 2.143 29.505 2.413 ;
     RECT  32.115 2.143 32.205 2.413 ;
     RECT  29.415 2.413 29.697 2.839 ;
     RECT  31.104 2.839 31.122 2.911 ;
     RECT  29.304 2.839 29.697 3.145 ;
     RECT  29.268 3.145 29.697 3.181 ;
     RECT  30.708 2.911 31.122 3.181 ;
     RECT  29.268 3.181 31.122 3.343 ;
     RECT  32.115 2.413 32.397 3.613 ;
     RECT  28.836 3.343 31.122 3.811 ;
     RECT  28.836 3.811 31.194 3.919 ;
     RECT  32.115 3.613 33.102 3.979 ;
     RECT  28.836 3.919 31.266 3.991 ;
     RECT  28.332 3.991 31.266 4.081 ;
     RECT  32.115 3.979 33.534 4.081 ;
     RECT  26.715 2.413 26.997 4.117 ;
     RECT  26.388 4.117 26.997 4.189 ;
     RECT  28.008 4.081 33.534 4.189 ;
     RECT  7.815 2.413 8.097 4.225 ;
     RECT  26.388 4.189 33.534 4.555 ;
     RECT  25.2 4.729 25.218 4.801 ;
     RECT  26.136 4.555 33.534 4.801 ;
     RECT  25.2 4.801 33.534 4.885 ;
     RECT  25.056 4.885 33.534 4.925 ;
     RECT  25.56 4.925 33.534 5.233 ;
     RECT  24.015 2.413 24.297 5.305 ;
     RECT  21.315 2.413 21.597 5.341 ;
     RECT  7.815 4.225 8.694 5.503 ;
     RECT  25.56 5.233 33.678 5.515 ;
     RECT  21.096 5.341 21.597 5.531 ;
     RECT  25.56 5.515 34.398 5.801 ;
     RECT  25.56 5.801 33.678 5.809 ;
     RECT  23.616 5.305 24.297 5.881 ;
     RECT  25.2 5.809 33.678 5.881 ;
     RECT  6.516 5.161 6.534 6.007 ;
     RECT  21.315 5.531 21.597 6.349 ;
     RECT  23.616 5.881 33.678 6.413 ;
     RECT  23.616 6.413 33.642 6.509 ;
     RECT  5.115 2.413 5.397 6.817 ;
     RECT  3.816 5.737 3.834 6.889 ;
     RECT  21.315 6.349 21.942 6.889 ;
     RECT  21.132 6.889 21.942 7.087 ;
     RECT  3.816 6.889 4.23 7.123 ;
     RECT  5.076 6.817 5.397 7.123 ;
     RECT  2.415 2.413 2.697 7.465 ;
     RECT  3.816 7.123 5.397 7.465 ;
     RECT  23.616 6.509 33.606 7.627 ;
     RECT  34.452 7.723 34.47 8.011 ;
     RECT  34.38 8.011 34.47 8.069 ;
     RECT  23.616 7.627 33.642 8.303 ;
     RECT  6.516 6.007 6.57 8.311 ;
     RECT  7.815 5.503 9.414 8.311 ;
     RECT  21.096 7.087 21.942 8.735 ;
     RECT  2.415 7.465 5.397 9.013 ;
     RECT  6.516 8.311 9.414 9.013 ;
     RECT  34.38 8.069 34.398 9.041 ;
     RECT  10.515 2.413 10.797 9.211 ;
     RECT  23.616 8.303 33.606 9.835 ;
     RECT  21.315 8.735 21.942 10.057 ;
     RECT  23.616 9.835 33.678 10.219 ;
     RECT  21.096 10.057 21.942 10.499 ;
     RECT  23.616 10.219 34.398 10.499 ;
     RECT  34.38 10.499 34.398 10.661 ;
     RECT  2.415 9.013 9.414 11.101 ;
     RECT  10.515 9.211 11.106 11.101 ;
     RECT  23.616 10.499 33.642 11.947 ;
     RECT  34.38 11.659 34.398 11.947 ;
     RECT  34.38 11.947 34.47 12.281 ;
     RECT  34.416 12.281 34.47 12.551 ;
     RECT  21.315 10.499 21.942 12.631 ;
     RECT  21.168 12.631 21.942 12.721 ;
     RECT  23.076 11.947 33.642 12.721 ;
     RECT  21.168 12.721 33.642 12.749 ;
     RECT  2.415 11.101 11.106 12.793 ;
     RECT  21.168 12.749 33.606 12.857 ;
     RECT  34.416 12.551 34.434 12.929 ;
     RECT  34.452 13.483 34.47 13.667 ;
     RECT  2.268 12.793 11.106 14.215 ;
     RECT  1.152 13.981 1.17 14.449 ;
     RECT  0.144 14.521 0.162 14.719 ;
     RECT  34.452 14.539 34.47 14.731 ;
     RECT  0.144 14.719 0.198 14.791 ;
     RECT  34.416 14.731 34.47 15.017 ;
     RECT  34.452 15.017 34.47 15.053 ;
     RECT  0.072 14.791 0.198 15.163 ;
     RECT  2.232 14.215 11.106 15.259 ;
     RECT  0.072 15.163 0.27 15.499 ;
     RECT  21.315 12.857 33.606 15.787 ;
     RECT  0.072 15.499 0.342 15.989 ;
     RECT  1.152 14.449 1.206 16.069 ;
     RECT  21.315 15.787 33.642 16.171 ;
     RECT  21.315 16.171 34.29 16.267 ;
     RECT  0.144 15.989 0.342 16.339 ;
     RECT  1.152 16.069 1.242 16.339 ;
     RECT  0.144 16.339 1.242 16.367 ;
     RECT  21.315 16.267 34.47 16.565 ;
     RECT  0.144 16.367 1.206 16.685 ;
     RECT  21.315 16.565 34.434 16.907 ;
     RECT  0.144 16.685 0.522 16.973 ;
     RECT  21.315 16.907 33.534 16.979 ;
     RECT  2.196 15.259 11.106 17.141 ;
     RECT  0.144 16.973 0.342 17.227 ;
     RECT  0.108 17.227 0.342 17.294 ;
     RECT  2.232 17.141 11.106 17.411 ;
     RECT  0.144 17.294 0.342 17.453 ;
     RECT  34.272 16.907 34.434 17.515 ;
     RECT  0.144 17.453 0.234 17.519 ;
     RECT  34.272 17.515 34.47 17.645 ;
     RECT  33.264 16.979 33.534 17.689 ;
     RECT  21.315 16.979 32.526 17.707 ;
     RECT  33.264 17.689 33.642 17.707 ;
     RECT  34.416 17.645 34.47 17.717 ;
     RECT  2.232 17.411 10.797 17.879 ;
     RECT  21.315 17.707 33.642 18.059 ;
     RECT  0.144 17.519 0.198 18.193 ;
     RECT  0.108 18.193 0.198 18.413 ;
     RECT  22.824 18.059 33.642 18.413 ;
     RECT  0.144 18.413 0.198 18.571 ;
     RECT  0.144 18.571 0.558 18.893 ;
     RECT  34.452 17.717 34.47 19.031 ;
     RECT  22.824 18.413 33.606 19.103 ;
     RECT  21.315 18.059 21.942 19.237 ;
     RECT  22.824 19.103 33.57 19.237 ;
     RECT  34.38 19.147 34.398 19.301 ;
     RECT  21.315 19.237 33.57 19.373 ;
     RECT  21.315 19.373 33.282 19.409 ;
     RECT  13.215 2.413 13.497 19.471 ;
     RECT  21.315 19.409 21.942 19.471 ;
     RECT  2.268 17.879 10.797 19.507 ;
     RECT  13.104 19.471 13.497 19.517 ;
     RECT  21.204 19.471 21.942 19.517 ;
     RECT  2.268 19.507 10.926 19.607 ;
     RECT  0.144 18.893 0.198 19.612 ;
     RECT  14.832 19.483 14.85 19.613 ;
     RECT  22.824 19.409 33.282 19.643 ;
     RECT  0.108 19.612 0.198 19.757 ;
     RECT  22.824 19.643 32.958 19.769 ;
     RECT  0.18 19.757 0.198 19.805 ;
     RECT  22.86 19.769 32.958 19.949 ;
     RECT  2.268 19.607 10.797 20.011 ;
     RECT  23.076 19.949 32.958 20.039 ;
     RECT  2.232 20.011 10.797 20.048 ;
     RECT  32.076 20.039 32.958 20.111 ;
     RECT  32.076 20.111 32.526 20.183 ;
     RECT  32.076 20.183 32.397 20.453 ;
     RECT  23.076 20.039 31.266 21.163 ;
     RECT  0.144 20.635 0.162 21.355 ;
     RECT  1.152 21.259 1.17 21.437 ;
     RECT  0.144 21.355 0.342 21.485 ;
     RECT  0.144 21.485 0.234 21.505 ;
     RECT  13.215 19.517 13.497 21.631 ;
     RECT  21.315 19.517 21.942 21.631 ;
     RECT  22.86 21.163 31.266 21.643 ;
     RECT  0.108 21.505 0.234 21.677 ;
     RECT  22.824 21.643 31.266 21.773 ;
     RECT  14.832 21.643 14.85 22.205 ;
     RECT  13.104 21.631 13.497 22.208 ;
     RECT  21.204 21.631 21.942 22.208 ;
     RECT  0.144 21.677 0.234 22.441 ;
     RECT  0.144 22.441 0.27 22.493 ;
     RECT  0.144 22.493 0.234 22.513 ;
     RECT  0.108 22.513 0.234 22.733 ;
     RECT  0.108 22.733 0.198 22.811 ;
     RECT  1.152 22.843 1.17 22.891 ;
     RECT  1.152 22.891 1.386 23.117 ;
     RECT  0.108 22.811 0.162 23.563 ;
     RECT  1.152 23.117 1.278 23.563 ;
     RECT  0.108 23.563 1.278 23.789 ;
     RECT  13.215 22.208 13.497 23.791 ;
     RECT  21.315 22.208 21.942 23.791 ;
     RECT  1.152 23.789 1.278 23.885 ;
     RECT  23.076 21.773 31.266 24.331 ;
     RECT  0.108 23.789 0.126 24.523 ;
     RECT  1.152 23.885 1.17 24.667 ;
     RECT  14.832 23.803 14.85 24.797 ;
     RECT  22.824 24.331 31.266 24.797 ;
     RECT  13.104 23.791 13.497 24.809 ;
     RECT  21.204 23.791 21.942 24.809 ;
     RECT  1.152 24.667 1.278 24.941 ;
     RECT  1.152 24.941 1.17 24.989 ;
     RECT  2.268 20.048 10.797 25.051 ;
     RECT  0.108 24.523 0.162 25.099 ;
     RECT  0.108 25.099 0.45 25.277 ;
     RECT  0.108 25.277 0.378 25.868 ;
     RECT  23.076 24.797 31.266 26.051 ;
     RECT  0.144 25.868 0.378 26.093 ;
     RECT  0.144 26.093 0.306 26.159 ;
     RECT  0.144 26.159 0.234 26.189 ;
     RECT  23.076 26.051 30.906 26.321 ;
     RECT  1.152 26.299 1.17 26.443 ;
     RECT  13.215 24.809 13.497 26.491 ;
     RECT  21.315 24.809 21.942 26.491 ;
     RECT  23.076 26.321 30.042 26.491 ;
     RECT  2.196 25.051 10.797 26.519 ;
     RECT  13.104 26.491 13.497 26.528 ;
     RECT  21.204 26.491 21.942 26.528 ;
     RECT  14.832 26.491 14.85 26.621 ;
     RECT  22.824 26.491 30.042 26.621 ;
     RECT  0.144 26.189 0.198 26.761 ;
     RECT  23.076 26.621 30.042 26.825 ;
     RECT  1.152 26.443 1.278 27.101 ;
     RECT  0.108 26.761 0.198 27.163 ;
     RECT  23.076 26.825 29.754 27.329 ;
     RECT  2.415 26.519 10.797 27.337 ;
     RECT  30.78 26.321 30.906 27.365 ;
     RECT  0.108 27.163 0.27 27.473 ;
     RECT  23.076 27.329 24.822 27.751 ;
     RECT  25.56 27.329 29.754 27.751 ;
     RECT  25.56 27.751 29.79 27.869 ;
     RECT  22.824 27.751 24.822 27.941 ;
     RECT  2.268 27.337 10.797 28.139 ;
     RECT  0.144 27.473 0.27 28.253 ;
     RECT  27.756 27.869 29.79 28.319 ;
     RECT  9.396 28.139 10.797 28.481 ;
     RECT  0.252 28.253 0.27 28.493 ;
     RECT  1.152 27.101 1.17 28.493 ;
     RECT  2.268 28.139 8.586 28.552 ;
     RECT  2.232 28.552 8.586 28.553 ;
     RECT  2.232 28.553 8.097 28.589 ;
     RECT  2.268 28.589 8.097 28.679 ;
     RECT  25.56 27.869 26.997 28.679 ;
     RECT  2.304 28.679 8.097 28.685 ;
     RECT  2.34 28.685 8.097 28.781 ;
     RECT  25.812 28.679 26.997 28.859 ;
     RECT  30.888 27.365 30.906 28.859 ;
     RECT  2.376 28.781 8.097 28.949 ;
     RECT  27.792 28.319 29.79 28.973 ;
     RECT  26.028 28.859 26.997 29.021 ;
     RECT  27.792 28.973 29.754 29.021 ;
     RECT  0.324 29.131 0.342 29.179 ;
     RECT  27.792 29.021 29.697 29.219 ;
     RECT  0.324 29.179 0.414 29.227 ;
     RECT  0.144 29.227 0.414 29.275 ;
     RECT  2.415 28.949 8.097 29.327 ;
     RECT  28.404 29.219 29.697 29.327 ;
     RECT  7.164 29.327 8.097 29.357 ;
     RECT  29.016 29.327 29.697 29.399 ;
     RECT  0.144 29.275 0.45 29.515 ;
     RECT  0.108 29.515 0.45 29.533 ;
     RECT  0.108 29.533 0.558 29.561 ;
     RECT  2.415 29.327 6.246 29.561 ;
     RECT  0.144 29.561 0.558 29.645 ;
     RECT  2.415 29.561 6.174 29.899 ;
     RECT  2.376 29.899 6.174 30.091 ;
     RECT  2.304 30.091 6.174 30.181 ;
     RECT  26.208 29.021 26.997 30.209 ;
     RECT  2.268 30.181 6.174 30.221 ;
     RECT  2.304 30.221 6.174 30.299 ;
     RECT  23.076 27.941 24.822 30.407 ;
     RECT  9.936 28.481 10.797 30.479 ;
     RECT  0.144 29.645 0.342 30.568 ;
     RECT  0.108 30.568 0.342 30.577 ;
     RECT  0.108 30.577 0.378 30.605 ;
     RECT  6.804 30.379 6.822 30.677 ;
     RECT  0.144 30.605 0.378 30.701 ;
     RECT  1.296 28.843 1.314 30.947 ;
     RECT  21.315 26.528 21.942 31.019 ;
     RECT  23.616 30.407 24.822 31.451 ;
     RECT  23.616 31.451 24.297 31.721 ;
     RECT  2.304 30.299 5.397 31.757 ;
     RECT  2.34 31.757 5.397 31.919 ;
     RECT  5.115 31.919 5.397 32.147 ;
     RECT  7.815 29.357 8.097 32.147 ;
     RECT  10.515 30.479 10.797 32.147 ;
     RECT  13.215 26.528 13.497 32.147 ;
     RECT  15.915 2.413 16.197 32.147 ;
     RECT  18.615 2.413 18.897 32.147 ;
     RECT  21.315 31.019 21.597 32.147 ;
     RECT  24.015 31.721 24.297 32.147 ;
     RECT  26.715 30.209 26.997 32.147 ;
     RECT  29.415 29.399 29.697 32.147 ;
     RECT  32.115 20.453 32.397 32.147 ;
     RECT  2.34 31.919 3.762 32.189 ;
     RECT  2.34 32.189 3.366 32.261 ;
     RECT  2.34 32.261 2.574 32.297 ;
     RECT  19.908 31.225 19.926 32.333 ;
     RECT  2.415 32.297 2.574 32.369 ;
     RECT  3.348 32.261 3.366 32.369 ;
     RECT  2.415 32.369 2.505 32.417 ;
     RECT  5.115 32.147 5.205 32.417 ;
     RECT  7.815 32.147 7.905 32.417 ;
     RECT  10.515 32.147 10.605 32.417 ;
     RECT  13.215 32.147 13.305 32.417 ;
     RECT  15.915 32.147 16.005 32.417 ;
     RECT  18.615 32.147 18.705 32.417 ;
     RECT  21.315 32.147 21.405 32.417 ;
     RECT  24.015 32.147 24.105 32.417 ;
     RECT  26.715 32.147 26.805 32.417 ;
     RECT  29.415 32.147 29.505 32.417 ;
     RECT  32.115 32.147 32.205 32.417 ;
    LAYER M4 ;
     RECT  0.06 15.216 0.169 30.696 ;
     RECT  0.169 15.168 0.281 30.696 ;
     RECT  0.281 15.216 2.293 30.696 ;
     RECT  2.293 14.784 2.408 30.696 ;
     RECT  2.408 2.148 2.512 32.412 ;
     RECT  2.512 2.418 2.704 32.142 ;
     RECT  2.704 15.504 3.161 31.368 ;
     RECT  3.161 31.344 3.241 31.368 ;
     RECT  3.161 15.504 3.413 30.312 ;
     RECT  2.704 7.152 4.357 7.368 ;
     RECT  3.413 15.984 4.453 30.312 ;
     RECT  2.704 4.704 5.108 4.728 ;
     RECT  4.357 6.816 5.108 7.368 ;
     RECT  2.704 11.76 5.108 11.784 ;
     RECT  4.453 15.984 5.108 31.128 ;
     RECT  5.108 2.148 5.212 32.412 ;
     RECT  5.212 2.418 5.404 32.142 ;
     RECT  5.404 18.144 5.465 19.512 ;
     RECT  5.404 16.896 5.681 17.16 ;
     RECT  5.404 20.688 5.681 29.784 ;
     RECT  5.681 26.496 5.825 29.784 ;
     RECT  5.681 20.688 5.897 25.512 ;
     RECT  5.897 21.072 5.933 25.512 ;
     RECT  5.933 21.072 5.969 25.368 ;
     RECT  5.465 18.528 6.041 19.512 ;
     RECT  6.041 18.768 6.221 19.512 ;
     RECT  5.825 26.592 6.329 29.784 ;
     RECT  5.969 21.12 6.509 25.368 ;
     RECT  6.221 19.488 6.829 19.512 ;
     RECT  5.404 4.704 7.808 4.728 ;
     RECT  5.404 6.816 7.808 7.368 ;
     RECT  5.404 11.76 7.808 11.784 ;
     RECT  5.681 16.896 7.808 16.92 ;
     RECT  6.829 19.488 7.808 19.608 ;
     RECT  6.509 21.12 7.808 24.936 ;
     RECT  6.329 26.592 7.808 26.616 ;
     RECT  6.329 27.6 7.808 29.784 ;
     RECT  7.808 2.148 7.912 32.412 ;
     RECT  7.912 2.418 8.104 32.142 ;
     RECT  8.104 4.704 10.508 4.728 ;
     RECT  8.104 6.816 10.508 7.368 ;
     RECT  8.104 11.76 10.508 11.784 ;
     RECT  8.104 16.896 10.508 16.92 ;
     RECT  8.104 19.584 10.508 19.608 ;
     RECT  8.104 21.12 10.508 24.936 ;
     RECT  8.104 26.592 10.508 26.616 ;
     RECT  8.104 27.6 10.508 29.784 ;
     RECT  10.508 2.148 10.612 32.412 ;
     RECT  10.612 2.418 10.804 32.142 ;
     RECT  10.804 4.704 13.208 4.728 ;
     RECT  10.804 6.816 13.208 7.368 ;
     RECT  10.804 11.76 13.208 11.784 ;
     RECT  10.804 16.896 13.208 16.92 ;
     RECT  10.804 19.488 13.208 19.512 ;
     RECT  10.804 21.12 13.208 24.936 ;
     RECT  10.804 26.496 13.208 26.52 ;
     RECT  10.804 27.6 13.208 29.784 ;
     RECT  13.208 2.148 13.312 32.412 ;
     RECT  13.312 2.418 13.504 32.142 ;
     RECT  13.504 19.488 14.821 19.512 ;
     RECT  13.504 26.496 14.821 26.52 ;
     RECT  14.821 19.488 14.861 19.608 ;
     RECT  14.821 26.496 14.861 26.616 ;
     RECT  13.504 4.704 15.908 4.728 ;
     RECT  13.504 6.816 15.908 7.368 ;
     RECT  13.504 11.76 15.908 11.784 ;
     RECT  13.504 16.896 15.908 16.92 ;
     RECT  14.861 19.584 15.908 19.608 ;
     RECT  13.504 21.12 15.908 24.936 ;
     RECT  14.861 26.592 15.908 26.616 ;
     RECT  13.504 27.6 15.908 29.784 ;
     RECT  15.908 2.148 16.012 32.412 ;
     RECT  16.012 2.418 16.204 32.142 ;
     RECT  16.204 11.76 17.893 11.784 ;
     RECT  16.204 4.704 18.608 4.728 ;
     RECT  16.204 6.816 18.608 7.368 ;
     RECT  17.893 11.76 18.608 12.504 ;
     RECT  16.204 16.896 18.608 16.92 ;
     RECT  16.204 19.584 18.608 19.608 ;
     RECT  16.204 21.12 18.608 24.936 ;
     RECT  16.204 26.592 18.608 26.616 ;
     RECT  16.204 27.6 18.608 29.784 ;
     RECT  17.989 32.304 18.608 32.328 ;
     RECT  18.608 2.148 18.712 32.412 ;
     RECT  18.712 2.418 18.904 32.328 ;
     RECT  18.904 32.304 19.937 32.328 ;
     RECT  18.904 4.704 21.308 4.728 ;
     RECT  18.904 6.816 21.308 7.368 ;
     RECT  18.904 11.76 21.308 12.504 ;
     RECT  18.904 16.896 21.308 16.92 ;
     RECT  18.904 19.488 21.308 19.512 ;
     RECT  18.904 21.12 21.308 24.936 ;
     RECT  18.904 26.496 21.308 26.52 ;
     RECT  18.904 27.6 21.308 29.784 ;
     RECT  21.308 2.148 21.412 32.412 ;
     RECT  21.412 2.418 21.604 32.142 ;
     RECT  21.604 19.488 22.813 19.512 ;
     RECT  21.604 26.496 22.813 26.52 ;
     RECT  22.813 19.488 22.853 19.608 ;
     RECT  22.813 26.496 22.853 26.616 ;
     RECT  21.604 4.704 24.008 4.728 ;
     RECT  21.604 6.816 24.008 7.368 ;
     RECT  21.604 11.76 24.008 12.504 ;
     RECT  21.604 16.896 24.008 16.92 ;
     RECT  22.853 19.584 24.008 19.608 ;
     RECT  21.604 21.12 24.008 24.936 ;
     RECT  22.853 26.592 24.008 26.616 ;
     RECT  21.604 27.6 24.008 29.784 ;
     RECT  24.008 2.148 24.112 32.412 ;
     RECT  24.112 2.418 24.304 32.142 ;
     RECT  24.304 27.6 24.797 29.784 ;
     RECT  24.304 19.584 25.085 19.608 ;
     RECT  24.304 16.416 25.235 16.92 ;
     RECT  24.304 6 25.301 8.28 ;
     RECT  25.301 6.24 25.405 8.28 ;
     RECT  24.304 9.264 25.405 9.288 ;
     RECT  24.304 10.848 26.089 12.504 ;
     RECT  25.693 15.12 26.089 15.48 ;
     RECT  24.304 18.048 26.089 18.072 ;
     RECT  24.304 4.704 26.125 4.92 ;
     RECT  25.405 6.24 26.149 9.288 ;
     RECT  26.089 10.848 26.161 13.08 ;
     RECT  26.149 6.24 26.444 9.768 ;
     RECT  26.161 10.848 26.444 13.128 ;
     RECT  26.125 4.56 26.708 4.92 ;
     RECT  26.444 6.24 26.708 13.128 ;
     RECT  26.089 14.208 26.708 15.48 ;
     RECT  25.235 16.512 26.708 16.92 ;
     RECT  26.089 18 26.708 18.072 ;
     RECT  24.304 21.12 26.708 24.936 ;
     RECT  24.304 26.592 26.708 26.616 ;
     RECT  24.797 27.6 26.708 29.016 ;
     RECT  26.708 2.148 26.812 32.412 ;
     RECT  26.812 2.418 27.004 32.142 ;
     RECT  27.004 21.12 27.677 24.936 ;
     RECT  27.004 4.704 27.997 19.848 ;
     RECT  27.004 26.592 28.573 26.616 ;
     RECT  27.004 27.6 28.573 29.016 ;
     RECT  27.997 4.704 28.825 19.944 ;
     RECT  28.885 3.312 29.077 3.336 ;
     RECT  28.825 4.704 29.077 19.992 ;
     RECT  29.077 3.312 29.125 19.992 ;
     RECT  27.677 21.12 29.125 22.056 ;
     RECT  29.125 3.312 29.408 22.056 ;
     RECT  27.677 23.04 29.408 24.936 ;
     RECT  28.573 26.592 29.408 29.016 ;
     RECT  29.408 2.148 29.512 32.412 ;
     RECT  29.512 2.418 29.704 32.142 ;
     RECT  29.704 28.512 29.801 28.968 ;
     RECT  29.704 21.216 29.909 22.056 ;
     RECT  29.704 4.704 30.017 19.608 ;
     RECT  29.909 21.504 30.233 21.528 ;
     RECT  29.704 23.04 30.269 23.064 ;
     RECT  29.704 3.312 30.341 3.384 ;
     RECT  30.017 4.704 30.377 19.56 ;
     RECT  30.341 3.36 30.413 3.384 ;
     RECT  30.377 4.704 30.449 19.464 ;
     RECT  30.449 5.424 30.557 19.464 ;
     RECT  30.557 5.424 30.845 17.064 ;
     RECT  30.557 18.048 30.845 19.464 ;
     RECT  30.845 5.424 30.881 13.992 ;
     RECT  30.881 5.424 30.989 9.96 ;
     RECT  30.845 15.072 31.849 17.064 ;
     RECT  30.845 18.048 31.849 19.32 ;
     RECT  30.989 7.104 31.957 9.96 ;
     RECT  30.881 11.088 31.957 13.992 ;
     RECT  30.989 5.424 32.108 5.88 ;
     RECT  31.957 7.104 32.108 13.992 ;
     RECT  31.849 15.072 32.108 19.32 ;
     RECT  32.108 2.148 32.212 32.412 ;
     RECT  32.212 2.418 32.404 32.142 ;
     RECT  32.404 3.792 34.524 19.272 ;
    LAYER M5 ;
     RECT  2.4 2.137 2.52 2.151 ;
     RECT  5.1 2.137 5.22 2.151 ;
     RECT  7.8 2.137 7.92 2.151 ;
     RECT  10.5 2.137 10.62 2.151 ;
     RECT  13.2 2.137 13.32 2.151 ;
     RECT  15.9 2.137 16.02 2.151 ;
     RECT  18.6 2.137 18.72 2.151 ;
     RECT  21.3 2.137 21.42 2.151 ;
     RECT  24 2.137 24.12 2.151 ;
     RECT  26.7 2.137 26.82 2.151 ;
     RECT  29.4 2.137 29.52 2.151 ;
     RECT  32.1 2.137 32.22 2.151 ;
     RECT  29.4 2.151 29.712 3.301 ;
     RECT  2.4 2.151 2.712 4.693 ;
     RECT  26.7 2.151 27.012 6.229 ;
     RECT  28.896 3.301 29.712 6.229 ;
     RECT  2.4 4.693 3.624 6.805 ;
     RECT  5.1 2.151 5.412 6.805 ;
     RECT  26.592 6.229 27.012 7.381 ;
     RECT  26.592 7.381 27.336 7.765 ;
     RECT  26.16 7.765 27.336 8.437 ;
     RECT  28.656 6.229 29.712 8.483 ;
     RECT  26.16 8.437 27.672 9.779 ;
     RECT  26.496 9.779 27.672 10.883 ;
     RECT  26.7 10.883 27.672 11.125 ;
     RECT  28.896 8.483 29.712 11.125 ;
     RECT  18.6 2.151 18.912 12.469 ;
     RECT  26.7 11.125 29.712 12.563 ;
     RECT  2.4 6.805 5.412 14.773 ;
     RECT  30.72 11.317 30.744 14.867 ;
     RECT  28.8 12.563 29.712 15.925 ;
     RECT  26.7 12.563 27.672 16.261 ;
     RECT  28.8 15.925 30.216 16.261 ;
     RECT  0.144 16.117 0.168 16.307 ;
     RECT  24 2.151 24.312 16.405 ;
     RECT  26.7 16.261 30.216 16.643 ;
     RECT  2.304 14.773 5.412 17.123 ;
     RECT  26.7 16.643 29.712 17.171 ;
     RECT  0.144 17.413 0.168 17.603 ;
     RECT  28.896 17.171 29.712 17.989 ;
     RECT  24 16.405 25.224 18.083 ;
     RECT  26.7 17.171 27.528 18.131 ;
     RECT  28.896 17.989 29.88 18.133 ;
     RECT  28.512 18.133 29.88 18.659 ;
     RECT  28.512 18.659 29.712 18.851 ;
     RECT  0.144 21.205 0.168 21.491 ;
     RECT  24 18.083 24.312 22.021 ;
     RECT  23.904 22.021 24.312 22.211 ;
     RECT  1.248 23.077 1.272 23.315 ;
     RECT  24 22.211 24.312 23.797 ;
     RECT  23.904 23.797 24.312 23.939 ;
     RECT  2.4 17.123 5.412 24.229 ;
     RECT  2.304 24.229 5.412 24.419 ;
     RECT  0.144 25.285 0.168 25.475 ;
     RECT  28.896 18.851 29.712 27.395 ;
     RECT  1.248 27.349 1.272 27.491 ;
     RECT  0.192 29.173 0.216 29.363 ;
     RECT  0.144 29.797 0.168 30.083 ;
     RECT  2.4 24.419 5.412 30.275 ;
     RECT  2.4 30.275 3.192 31.379 ;
     RECT  2.4 31.379 2.712 32.409 ;
     RECT  5.1 30.275 5.412 32.409 ;
     RECT  7.8 2.151 8.112 32.409 ;
     RECT  10.5 2.151 10.812 32.409 ;
     RECT  13.2 2.151 13.512 32.409 ;
     RECT  15.9 2.151 16.212 32.409 ;
     RECT  17.904 12.469 18.912 32.409 ;
     RECT  21.3 2.151 21.612 32.409 ;
     RECT  24 23.939 24.312 32.409 ;
     RECT  26.7 18.131 27.012 32.409 ;
     RECT  29.4 27.395 29.712 32.409 ;
     RECT  32.1 2.151 32.412 32.409 ;
     RECT  2.4 32.409 2.52 32.423 ;
     RECT  5.1 32.409 5.22 32.423 ;
     RECT  7.8 32.409 7.92 32.423 ;
     RECT  10.5 32.409 10.62 32.423 ;
     RECT  13.2 32.409 13.32 32.423 ;
     RECT  15.9 32.409 16.02 32.423 ;
     RECT  17.904 32.409 18.72 32.423 ;
     RECT  21.3 32.409 21.42 32.423 ;
     RECT  24 32.409 24.12 32.423 ;
     RECT  26.7 32.409 26.82 32.423 ;
     RECT  29.4 32.409 29.52 32.423 ;
     RECT  32.1 32.409 32.22 32.423 ;
     RECT  17.904 32.423 18.024 34.512 ;
  END
END ot_hgi_coll_inj_copy
END LIBRARY
